VERSION 5.8 ;
BUSBITCHARS "[]" ;
DIVIDERCHAR "/" ;

UNITS
  DATABASE MICRONS 1000 ;
END UNITS
MANUFACTURINGGRID 0.001 ;

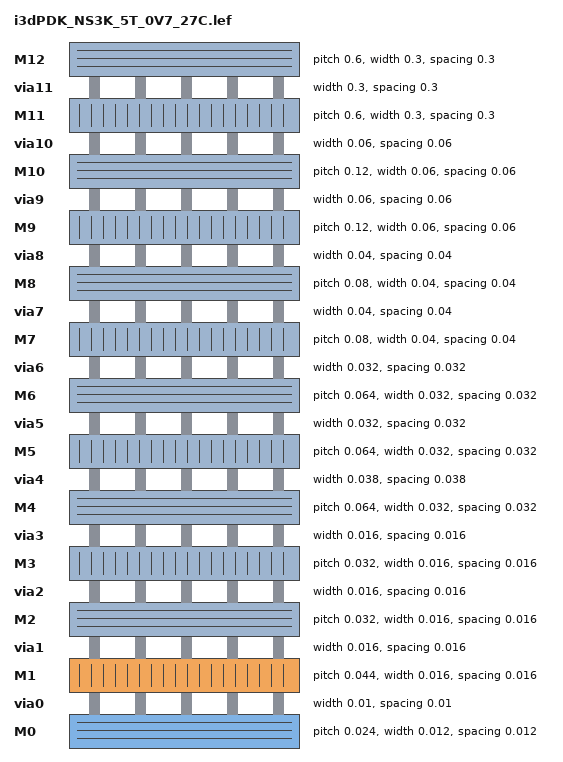
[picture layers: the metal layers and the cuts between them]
LAYER M0
  TYPE ROUTING ;
  DIRECTION HORIZONTAL ;
  PITCH 0.024 0.024 ;
  WIDTH 0.012 ;
  OFFSET 0.012 0.012 ;
  AREA 0.000144 ;
  SPACING 0.012 ;
  MAXWIDTH 5 ;
  RESISTANCE RPERSQ 2.53 ;
END M0

LAYER via0
  TYPE CUT ;
  SPACING 0.01 ;
  WIDTH 0.01 ;
  RESISTANCE 19.304 ;
END via0

LAYER M1
  TYPE ROUTING ;
  DIRECTION VERTICAL ;
  PITCH 0.044 0.044 ;
  WIDTH 0.016 ;
  OFFSET 0.016 0.016 ;
  AREA 0.000256 ;
  SPACING 0.016 ;
  MAXWIDTH 5 ;
  RESISTANCE RPERSQ 1.41 ;
END M1

LAYER via1
  TYPE CUT ;
  SPACING 0.016 ;
  WIDTH 0.016 ;
  RESISTANCE 8.56 ;
END via1

LAYER M2
  TYPE ROUTING ;
  DIRECTION HORIZONTAL ;
  PITCH 0.032 0.032 ;
  WIDTH 0.016 ;
  OFFSET 0.016 0.016 ;
  AREA 0.000256 ;
  SPACING 0.016 ;
  MAXWIDTH 5 ;
  RESISTANCE RPERSQ 1.41 ;
END M2

LAYER via2
  TYPE CUT ;
  SPACING 0.016 ;
  WIDTH 0.016 ;
  RESISTANCE 8.56 ;
END via2

LAYER M3
  TYPE ROUTING ;
  DIRECTION VERTICAL ;
  PITCH 0.032 0.032 ;
  WIDTH 0.016 ;
  OFFSET 0.016 0.016 ;
  AREA 0.000256 ;
  SPACING 0.016 ;
  MAXWIDTH 5 ;
  RESISTANCE RPERSQ 1.41 ;
END M3

LAYER via3
  TYPE CUT ;
  SPACING 0.016 ;
  WIDTH 0.016 ;
  RESISTANCE 8.56 ;
END via3

LAYER M4
  TYPE ROUTING ;
  DIRECTION HORIZONTAL ;
  PITCH 0.064 0.064 ;
  WIDTH 0.032 ;
  OFFSET 0.032 0.032 ;
  AREA 0.001024 ;
  SPACING 0.032 ;
  MAXWIDTH 5 ;
  RESISTANCE RPERSQ 0.52 ;
END M4

LAYER via4
  TYPE CUT ;
  SPACING 0.038 ;
  WIDTH 0.038 ;
  RESISTANCE 2.82 ;
END via4

LAYER M5
  TYPE ROUTING ;
  DIRECTION VERTICAL ;
  PITCH 0.064 0.064 ;
  WIDTH 0.032 ;
  OFFSET 0.032 0.032 ;
  AREA 0.001024 ;
  SPACING 0.032 ;
  MAXWIDTH 5 ;
  RESISTANCE RPERSQ 0.52 ;
END M5

LAYER via5
  TYPE CUT ;
  SPACING 0.032 ;
  WIDTH 0.032 ;
  RESISTANCE 2.82 ;
END via5

LAYER M6
  TYPE ROUTING ;
  DIRECTION HORIZONTAL ;
  PITCH 0.064 0.064 ;
  WIDTH 0.032 ;
  OFFSET 0.032 0.032 ;
  AREA 0.001024 ;
  SPACING 0.032 ;
  MAXWIDTH 5 ;
  RESISTANCE RPERSQ 0.52 ;
END M6

LAYER via6
  TYPE CUT ;
  SPACING 0.032 ;
  WIDTH 0.032 ;
  RESISTANCE 2.82 ;
END via6

LAYER M7
  TYPE ROUTING ;
  DIRECTION VERTICAL ;
  PITCH 0.08 0.08 ;
  WIDTH 0.04 ;
  OFFSET 0.04 0.04 ;
  AREA 0.0016 ;
  SPACING 0.04 ;
  MAXWIDTH 5 ;
  RESISTANCE RPERSQ 0.386 ;
END M7

LAYER via7
  TYPE CUT ;
  SPACING 0.04 ;
  WIDTH 0.04 ;
  RESISTANCE 2.02 ;
END via7

LAYER M8
  TYPE ROUTING ;
  DIRECTION HORIZONTAL ;
  PITCH 0.08 0.08 ;
  WIDTH 0.04 ;
  OFFSET 0.04 0.04 ;
  AREA 0.0016 ;
  SPACING 0.04 ;
  MAXWIDTH 5 ;
  RESISTANCE RPERSQ 0.386 ;
END M8

LAYER via8
  TYPE CUT ;
  SPACING 0.04 ;
  WIDTH 0.04 ;
  RESISTANCE 2.02 ;
END via8

LAYER M9
  TYPE ROUTING ;
  DIRECTION VERTICAL ;
  PITCH 0.12 0.12 ;
  WIDTH 0.06 ;
  OFFSEt 0.06 0.06 ;
  AREA 0.0036 ;
  SPACING 0.06 ;
  MAXWIDTH 5 ;
  RESISTANCE RPERSQ 0.23 ;
END M9

LAYER via9
  TYPE CUT ;
  SPACING 0.06 ;
  WIDTH 0.06 ;
  RESISTANCE 1.136 ;
END via9

LAYER M10
  TYPE ROUTING ;
  DIRECTION HORIZONTAL ;
  PITCH 0.12 0.12 ;
  WIDTH 0.06 ;
  OFFSET 0.06 0.06 ;
  AREA 0.0036 ;
  SPACING 0.06 ;
  MAXWIDTH 5 ;
  RESISTANCE RPERSQ 0.23 ;
END M10

LAYER via10
  TYPE CUT ;
  SPACING 0.06 ;
  WIDTH 0.06 ;
  RESISTANCE 1.136 ;
END via10

LAYER M11
  TYPE ROUTING ;
  DIRECTION VERTICAL ;
  PITCH 0.6 0.6 ;
  WIDTH 0.3 ;
  OFFSET 0.3 0.3 ;
  AREA 0.09 ;
  SPACING 0.3 ;
  MAXWIDTH 5 ;
  RESISTANCE RPERSQ 0.037 ;
END M11

LAYER via11
  TYPE CUT ;
  SPACING 0.3 ;
  WIDTH 0.3 ;
  RESISTANCE 0.158 ;
END via11

LAYER M12
  TYPE ROUTING ;
  DIRECTION HORIZONTAL ;
  PITCH 0.6 0.6 ;
  WIDTH 0.3 ;
  OFFSET 0.3 0.3 ;
  AREA 0.09 ;
  SPACING 0.3 ;
  MAXWIDTH 5 ;
  RESISTANCE RPERSQ 0.037 ;
END M12

SITE i3d_nsfet3nm
  SYMMETRY y ;
  CLASS core ;
  SIZE 0.044 BY 0.12 ;
END i3d_nsfet3nm


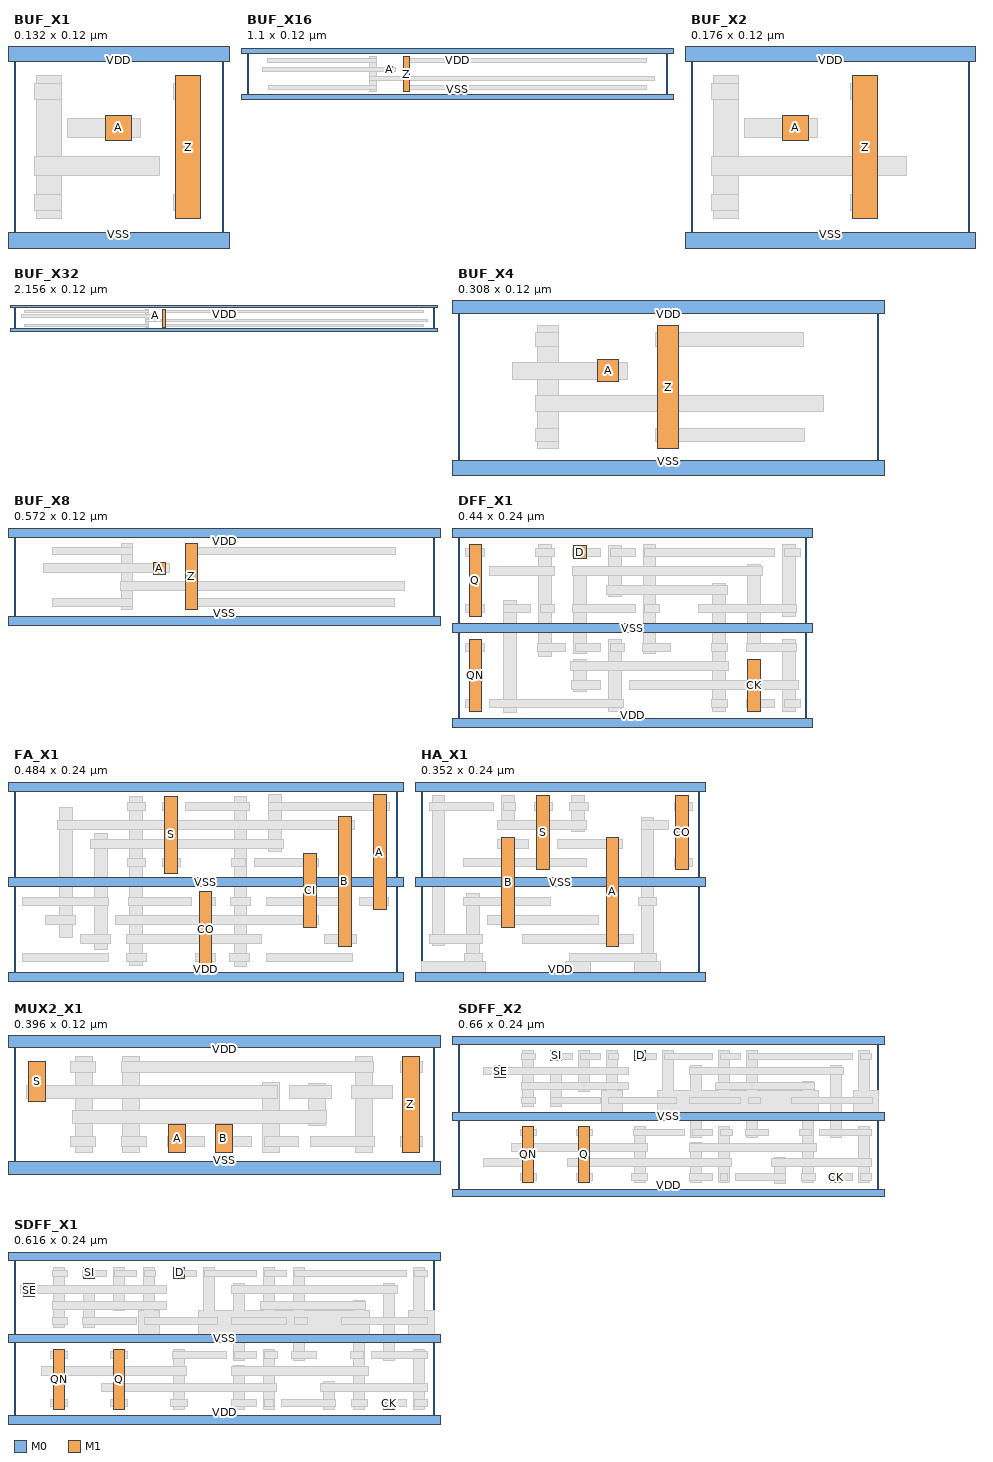
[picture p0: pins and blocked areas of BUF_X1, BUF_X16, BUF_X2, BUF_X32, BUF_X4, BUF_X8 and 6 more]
MACRO BUF_X1
  CLASS CORE ;
  ORIGIN 0 0 ;
  FOREIGN BUF_X1 0 0 ;
  SYMMETRY X Y ;
  SITE i3d_nsfet3nm ;
  SIZE 0.132 BY 0.12 ;
  PIN VDD
    DIRECTION INOUT ;
    USE POWER ;
    PORT
      LAYER M0 ;
        RECT -0.016 0.114 0.148 0.126 ;
    END
  END VDD
  PIN VSS
    DIRECTION INOUT ;
    USE GROUND ;
    PORT
      LAYER M0 ;
        RECT -0.016 -0.006 0.148 0.006 ;
    END
  END VSS
  PIN A
    DIRECTION INPUT ;
    USE SIGNAL ;
    PORT
      LAYER M1 ;
        RECT 0.058 0.064 0.074 0.08 ;
    END
  END A
  PIN Z
    DIRECTION OUTPUT ;
    USE SIGNAL ;
    PORT
      LAYER M1 ;
        RECT 0.102 0.015 0.118 0.105 ;
    END
  END Z
  OBS
    LAYER M1 DESIGNRULEWIDTH 0 ;
      RECT 0.014 0.015 0.03 0.105 ;
    LAYER M0 DESIGNRULEWIDTH 0 ;
      RECT 0.101 0.02 0.118 0.03 ;
      RECT 0.013 0.02 0.03 0.03 ;
      RECT 0.013 0.042 0.092 0.054 ;
      RECT 0.034 0.066 0.08 0.078 ;
      RECT 0.101 0.09 0.118 0.1 ;
      RECT 0.013 0.09 0.03 0.1 ;
  END
END BUF_X1

MACRO BUF_X16
  CLASS CORE ;
  ORIGIN 0 0 ;
  FOREIGN BUF_X16 0 0 ;
  SYMMETRY X Y ;
  SITE i3d_nsfet3nm ;
  SIZE 1.1 BY 0.12 ;
  PIN VDD
    DIRECTION INOUT ;
    USE POWER ;
    PORT
      LAYER M0 ;
        RECT -0.016 0.114 1.116 0.126 ;
    END
  END VDD
  PIN VSS
    DIRECTION INOUT ;
    USE GROUND ;
    PORT
      LAYER M0 ;
        RECT -0.016 -0.006 1.116 0.006 ;
    END
  END VSS
  PIN A
    DIRECTION INPUT ;
    USE SIGNAL ;
    PORT
      LAYER M1 ;
        RECT 0.366 0.064 0.382 0.08 ;
    END
  END A
  PIN Z
    DIRECTION OUTPUT ;
    USE SIGNAL ;
    PORT
      LAYER M1 ;
        RECT 0.41 0.015 0.426 0.105 ;
    END
  END Z
  OBS
    LAYER M1 DESIGNRULEWIDTH 0 ;
      RECT 0.322 0.015 0.338 0.105 ;
    LAYER M0 DESIGNRULEWIDTH 0 ;
      RECT 0.409 0.02 1.046 0.03 ;
      RECT 0.056 0.02 0.338 0.03 ;
      RECT 0.321 0.042 1.066 0.054 ;
      RECT 0.04 0.066 0.388 0.078 ;
      RECT 0.409 0.09 1.047 0.1 ;
      RECT 0.053 0.09 0.338 0.1 ;
  END
END BUF_X16

MACRO BUF_X2
  CLASS CORE ;
  ORIGIN 0 0 ;
  FOREIGN BUF_X2 0 0 ;
  SYMMETRY X Y ;
  SITE i3d_nsfet3nm ;
  SIZE 0.176 BY 0.12 ;
  PIN VDD
    DIRECTION INOUT ;
    USE POWER ;
    PORT
      LAYER M0 ;
        RECT -0.016 0.114 0.192 0.126 ;
    END
  END VDD
  PIN VSS
    DIRECTION INOUT ;
    USE GROUND ;
    PORT
      LAYER M0 ;
        RECT -0.016 -0.006 0.192 0.006 ;
    END
  END VSS
  PIN A
    DIRECTION INPUT ;
    USE SIGNAL ;
    PORT
      LAYER M1 ;
        RECT 0.058 0.064 0.074 0.08 ;
    END
  END A
  PIN Z
    DIRECTION OUTPUT ;
    USE SIGNAL ;
    PORT
      LAYER M1 ;
        RECT 0.102 0.015 0.118 0.105 ;
    END
  END Z
  OBS
    LAYER M1 DESIGNRULEWIDTH 0 ;
      RECT 0.014 0.015 0.03 0.105 ;
    LAYER M0 DESIGNRULEWIDTH 0 ;
      RECT 0.101 0.02 0.118 0.03 ;
      RECT 0.013 0.02 0.03 0.03 ;
      RECT 0.013 0.042 0.136 0.054 ;
      RECT 0.034 0.066 0.08 0.078 ;
      RECT 0.101 0.09 0.118 0.1 ;
      RECT 0.013 0.09 0.03 0.1 ;
  END
END BUF_X2

MACRO BUF_X32
  CLASS CORE ;
  ORIGIN 0 0 ;
  FOREIGN BUF_X32 0 0 ;
  SYMMETRY X Y ;
  SITE i3d_nsfet3nm ;
  SIZE 2.156 BY 0.12 ;
  PIN VDD
    DIRECTION INOUT ;
    USE POWER ;
    PORT
      LAYER M0 ;
        RECT -0.016 0.114 2.172 0.126 ;
    END
  END VDD
  PIN VSS
    DIRECTION INOUT ;
    USE GROUND ;
    PORT
      LAYER M0 ;
        RECT -0.016 -0.006 2.172 0.006 ;
    END
  END VSS
  PIN Z
    DIRECTION OUTPUT ;
    USE SIGNAL ;
    PORT
      LAYER M1 ;
        RECT 0.762 0.015 0.778 0.105 ;
    END
  END Z
  PIN A
    DIRECTION INPUT ;
    USE SIGNAL ;
    PORT
      LAYER M1 ;
        RECT 0.718 0.064 0.734 0.08 ;
    END
  END A
  OBS
    LAYER M1 DESIGNRULEWIDTH 0 ;
      RECT 0.674 0.015 0.69 0.105 ;
    LAYER M0 DESIGNRULEWIDTH 0 ;
      RECT 0.761 0.02 2.104 0.03 ;
      RECT 0.055 0.02 0.69 0.03 ;
      RECT 0.673 0.042 2.123 0.054 ;
      RECT 0.039 0.066 0.74 0.078 ;
      RECT 0.761 0.09 2.101 0.1 ;
      RECT 0.053 0.09 0.69 0.1 ;
  END
END BUF_X32

MACRO BUF_X4
  CLASS CORE ;
  ORIGIN 0 0 ;
  FOREIGN BUF_X4 0 0 ;
  SYMMETRY X Y ;
  SITE i3d_nsfet3nm ;
  SIZE 0.308 BY 0.12 ;
  PIN VDD
    DIRECTION INOUT ;
    USE POWER ;
    PORT
      LAYER M0 ;
        RECT -0.016 0.114 0.324 0.126 ;
    END
  END VDD
  PIN VSS
    DIRECTION INOUT ;
    USE GROUND ;
    PORT
      LAYER M0 ;
        RECT -0.016 -0.006 0.324 0.006 ;
    END
  END VSS
  PIN A
    DIRECTION INPUT ;
    USE SIGNAL ;
    PORT
      LAYER M1 ;
        RECT 0.102 0.064 0.118 0.08 ;
    END
  END A
  PIN Z
    DIRECTION OUTPUT ;
    USE SIGNAL ;
    PORT
      LAYER M1 ;
        RECT 0.146 0.015 0.162 0.105 ;
    END
  END Z
  OBS
    LAYER M1 DESIGNRULEWIDTH 0 ;
      RECT 0.058 0.015 0.074 0.105 ;
    LAYER M0 DESIGNRULEWIDTH 0 ;
      RECT 0.145 0.02 0.254 0.03 ;
      RECT 0.057 0.02 0.074 0.03 ;
      RECT 0.057 0.042 0.268 0.054 ;
      RECT 0.04 0.066 0.124 0.078 ;
      RECT 0.145 0.09 0.253 0.1 ;
      RECT 0.057 0.09 0.074 0.1 ;
  END
END BUF_X4

MACRO BUF_X8
  CLASS CORE ;
  ORIGIN 0 0 ;
  FOREIGN BUF_X8 0 0 ;
  SYMMETRY X Y ;
  SITE i3d_nsfet3nm ;
  SIZE 0.572 BY 0.12 ;
  PIN VDD
    DIRECTION INOUT ;
    USE POWER ;
    PORT
      LAYER M0 ;
        RECT -0.016 0.114 0.588 0.126 ;
    END
  END VDD
  PIN VSS
    DIRECTION INOUT ;
    USE GROUND ;
    PORT
      LAYER M0 ;
        RECT -0.016 -0.006 0.588 0.006 ;
    END
  END VSS
  PIN A
    DIRECTION INPUT ;
    USE SIGNAL ;
    PORT
      LAYER M1 ;
        RECT 0.19 0.064 0.206 0.08 ;
    END
  END A
  PIN Z
    DIRECTION OUTPUT ;
    USE SIGNAL ;
    PORT
      LAYER M1 ;
        RECT 0.234 0.015 0.25 0.105 ;
    END
  END Z
  OBS
    LAYER M1 DESIGNRULEWIDTH 0 ;
      RECT 0.146 0.015 0.162 0.105 ;
    LAYER M0 DESIGNRULEWIDTH 0 ;
      RECT 0.233 0.02 0.518 0.03 ;
      RECT 0.052 0.02 0.162 0.03 ;
      RECT 0.145 0.042 0.532 0.054 ;
      RECT 0.04 0.066 0.212 0.078 ;
      RECT 0.233 0.09 0.519 0.1 ;
      RECT 0.052 0.09 0.162 0.1 ;
  END
END BUF_X8

MACRO DFF_X1
  CLASS CORE ;
  ORIGIN 0 0 ;
  FOREIGN DFF_X1 0 0 ;
  SYMMETRY X Y ;
  SITE i3d_nsfet3nm ;
  SIZE 0.44 BY 0.24 ;
  PIN Q
    DIRECTION OUTPUT ;
    USE SIGNAL ;
    PORT
      LAYER M1 ;
        RECT 0.014 0.135 0.03 0.225 ;
    END
  END Q
  PIN VDD
    DIRECTION INOUT ;
    USE POWER ;
    PORT
      LAYER M0 ;
        RECT -0.016 0.234 0.456 0.246 ;
        RECT -0.016 -0.006 0.456 0.006 ;
    END
  END VDD
  PIN VSS
    DIRECTION INOUT ;
    USE GROUND ;
    PORT
      LAYER M0 ;
        RECT -0.016 0.114 0.456 0.126 ;
    END
  END VSS
  PIN D
    DIRECTION INPUT ;
    USE SIGNAL ;
    PORT
      LAYER M1 ;
        RECT 0.146 0.208 0.162 0.224 ;
    END
  END D
  PIN QN
    DIRECTION OUTPUT ;
    USE SIGNAL ;
    PORT
      LAYER M1 ;
        RECT 0.014 0.015 0.03 0.105 ;
    END
  END QN
  PIN CK
    DIRECTION INPUT ;
    USE SIGNAL ;
    PORT
      LAYER M1 ;
        RECT 0.366 0.015 0.382 0.08 ;
    END
  END CK
  OBS
    LAYER M1 ;
      RECT 0.058 0.013 0.074 0.155 ;
      RECT 0.19 0.015 0.206 0.105 ;
      RECT 0.322 0.015 0.338 0.176 ;
      RECT 0.41 0.015 0.426 0.105 ;
      RECT 0.146 0.04 0.162 0.08 ;
      RECT 0.102 0.084 0.118 0.225 ;
      RECT 0.146 0.088 0.162 0.188 ;
      RECT 0.234 0.088 0.25 0.225 ;
      RECT 0.366 0.1 0.382 0.2 ;
      RECT 0.41 0.135 0.426 0.225 ;
      RECT 0.19 0.16 0.206 0.224 ;
    LAYER M0 ;
      RECT 0.01 0.02 0.028 0.03 ;
      RECT 0.04 0.02 0.209 0.03 ;
      RECT 0.32 0.02 0.34 0.03 ;
      RECT 0.365 0.02 0.4 0.03 ;
      RECT 0.412 0.02 0.432 0.03 ;
      RECT 0.143 0.042 0.18 0.054 ;
      RECT 0.216 0.042 0.43 0.054 ;
      RECT 0.142 0.066 0.342 0.078 ;
      RECT 0.01 0.09 0.034 0.1 ;
      RECT 0.1 0.09 0.136 0.1 ;
      RECT 0.148 0.09 0.18 0.1 ;
      RECT 0.192 0.09 0.21 0.1 ;
      RECT 0.233 0.09 0.268 0.1 ;
      RECT 0.32 0.09 0.34 0.1 ;
      RECT 0.364 0.09 0.428 0.1 ;
      RECT 0.01 0.14 0.034 0.15 ;
      RECT 0.057 0.14 0.092 0.15 ;
      RECT 0.104 0.14 0.122 0.15 ;
      RECT 0.144 0.14 0.224 0.15 ;
      RECT 0.236 0.14 0.255 0.15 ;
      RECT 0.304 0.14 0.428 0.15 ;
      RECT 0.187 0.162 0.34 0.174 ;
      RECT 0.04 0.186 0.122 0.198 ;
      RECT 0.145 0.186 0.384 0.198 ;
      RECT 0.01 0.21 0.034 0.22 ;
      RECT 0.098 0.21 0.122 0.22 ;
      RECT 0.144 0.21 0.18 0.22 ;
      RECT 0.192 0.21 0.224 0.22 ;
      RECT 0.236 0.21 0.4 0.22 ;
      RECT 0.412 0.21 0.432 0.22 ;
  END
END DFF_X1


MACRO FA_X1
  CLASS CORE ;
  ORIGIN 0 0 ;
  FOREIGN FA 0 0 ;
  SYMMETRY X Y ;
  SITE i3d_nsfet3nm ;
  SIZE 0.484 BY 0.24 ;
  PIN VDD
    DIRECTION INOUT ;
    USE POWER ;
    PORT
      LAYER M0 ;
        RECT -0.016 -0.006 0.5 0.006 ;
        RECT -0.016 0.234 0.5 0.246 ;
    END
  END VDD
  PIN VSS
    DIRECTION INOUT ;
    USE GROUND ;
    PORT
      LAYER M0 ;
        RECT -0.016 0.114 0.5 0.126 ;
    END
  END VSS
  PIN CO
    DIRECTION OUTPUT ;
    USE SIGNAL ;
    PORT
      LAYER M1 ;
        RECT 0.234 0.013 0.25 0.108 ;
    END
  END CO
  PIN CI
    DIRECTION INPUT ;
    USE SIGNAL ;
    PORT
      LAYER M1 ;
        RECT 0.366 0.063 0.382 0.156 ;
    END
  END CI
  PIN A
    DIRECTION INPUT ;
    USE SIGNAL ;
    PORT
      LAYER M1 ;
        RECT 0.454 0.085 0.47 0.23 ;
    END
  END A
  PIN B
    DIRECTION INPUT ;
    USE SIGNAL ;
    PORT
      LAYER M1 ;
        RECT 0.41 0.039 0.426 0.203 ;
    END
  END B
  PIN S
    DIRECTION OUTPUT ;
    USE SIGNAL ;
    PORT
      LAYER M1 ;
        RECT 0.19 0.131 0.206 0.228 ;
    END
  END S
  OBS
    LAYER M1 DESIGNRULEWIDTH 0 ;
      RECT 0.278 0.013 0.294 0.228 ;
      RECT 0.146 0.014 0.162 0.228 ;
      RECT 0.102 0.035 0.118 0.181 ;
      RECT 0.058 0.05 0.074 0.214 ;
      RECT 0.322 0.159 0.338 0.23 ;
    LAYER M0 DESIGNRULEWIDTH 0 ;
      RECT 0.319 0.02 0.427 0.03 ;
      RECT 0.272 0.02 0.297 0.03 ;
      RECT 0.229 0.02 0.254 0.03 ;
      RECT 0.142 0.02 0.167 0.03 ;
      RECT 0.011 0.02 0.119 0.03 ;
      RECT 0.392 0.042 0.432 0.054 ;
      RECT 0.142 0.042 0.312 0.054 ;
      RECT 0.084 0.042 0.122 0.054 ;
      RECT 0.128 0.066 0.384 0.078 ;
      RECT 0.04 0.066 0.078 0.078 ;
      RECT 0.436 0.09 0.473 0.1 ;
      RECT 0.319 0.09 0.424 0.1 ;
      RECT 0.274 0.09 0.299 0.1 ;
      RECT 0.236 0.09 0.254 0.1 ;
      RECT 0.144 0.09 0.224 0.1 ;
      RECT 0.011 0.09 0.119 0.1 ;
      RECT 0.304 0.14 0.384 0.15 ;
      RECT 0.275 0.14 0.292 0.15 ;
      RECT 0.187 0.14 0.21 0.15 ;
      RECT 0.143 0.14 0.166 0.15 ;
      RECT 0.097 0.162 0.34 0.174 ;
      RECT 0.055 0.186 0.43 0.198 ;
      RECT 0.321 0.21 0.474 0.22 ;
      RECT 0.216 0.21 0.298 0.22 ;
      RECT 0.187 0.21 0.204 0.22 ;
      RECT 0.143 0.21 0.166 0.22 ;
  END
END FA_X1

MACRO HA_X1
  CLASS CORE ;
  ORIGIN 0 0 ;
  FOREIGN HA 0 0 ;
  SYMMETRY X Y ;
  SITE i3d_nsfet3nm ;
  SIZE 0.352 BY 0.24 ;
  PIN VDD
    DIRECTION INOUT ;
    USE POWER ;
    PORT
      LAYER M0 ;
        RECT -0.016 -0.006 0.368 0.006 ;
        RECT -0.016 0.234 0.368 0.246 ;
    END
  END VDD
  PIN S
    DIRECTION OUTPUT ;
    USE SIGNAL ;
    PORT
      LAYER M1 ;
        RECT 0.146 0.136 0.162 0.229 ;
    END
  END S
  PIN B
    DIRECTION INPUT ;
    USE SIGNAL ;
    PORT
      LAYER M1 ;
        RECT 0.102 0.063 0.118 0.176 ;
    END
  END B
  PIN A
    DIRECTION INPUT ;
    USE SIGNAL ;
    PORT
      LAYER M1 ;
        RECT 0.234 0.039 0.25 0.176 ;
    END
  END A
  PIN VSS
    DIRECTION INOUT ;
    USE GROUND ;
    PORT
      LAYER M0 ;
        RECT -0.016 0.114 0.368 0.126 ;
    END
  END VSS
  PIN CO
    DIRECTION OUTPUT ;
    USE SIGNAL ;
    PORT
      LAYER M1 ;
        RECT 0.322 0.136 0.338 0.229 ;
    END
  END CO
  OBS
    LAYER M1 DESIGNRULEWIDTH 0 ;
      POLYGON 0.302 0 0.302 0.019 0.294 0.019 0.294 0.201 0.278 0.201 0.278 0.019 0.27 0.019 0.27 0 ;
      RECT 0.182 0 0.214 0.019 ;
      POLYGON 0.082 0 0.082 0.019 0.074 0.019 0.074 0.105 0.058 0.105 0.058 0.019 0 0.019 0 0 ;
      RECT 0.014 0.04 0.03 0.229 ;
      RECT 0.19 0.184 0.206 0.229 ;
      RECT 0.102 0.196 0.118 0.229 ;
    LAYER M0 DESIGNRULEWIDTH 0 ;
      RECT 0.187 0.02 0.298 0.03 ;
      RECT 0.055 0.02 0.078 0.03 ;
      RECT 0.128 0.042 0.268 0.054 ;
      RECT 0.011 0.042 0.078 0.054 ;
      RECT 0.084 0.066 0.224 0.078 ;
      RECT 0.275 0.09 0.298 0.1 ;
      RECT 0.054 0.09 0.164 0.1 ;
      RECT 0.32 0.14 0.343 0.15 ;
      RECT 0.054 0.14 0.209 0.15 ;
      RECT 0.172 0.162 0.254 0.174 ;
      RECT 0.097 0.162 0.136 0.174 ;
      RECT 0.278 0.186 0.312 0.198 ;
      RECT 0.097 0.186 0.209 0.198 ;
      RECT 0.32 0.21 0.343 0.22 ;
      RECT 0.188 0.21 0.211 0.22 ;
      RECT 0.143 0.21 0.166 0.22 ;
      RECT 0.104 0.21 0.119 0.22 ;
      RECT 0.011 0.21 0.092 0.22 ;
  END
END HA_X1

MACRO MUX2_X1
  CLASS CORE ;
  ORIGIN 0 0 ;
  FOREIGN MUX2_X1 0 0 ;
  SYMMETRY X Y ;
  SITE i3d_nsfet3nm ;
  SIZE 0.396 BY 0.12 ;
  PIN VDD
    DIRECTION INOUT ;
    USE POWER ;
    PORT
      LAYER M0 ;
        RECT -0.016 0.114 0.412 0.126 ;
    END
  END VDD
  PIN VSS
    DIRECTION INOUT ;
    USE GROUND ;
    PORT
      LAYER M0 ;
        RECT -0.016 -0.006 0.412 0.006 ;
    END
  END VSS
  PIN A
    DIRECTION INPUT ;
    USE SIGNAL ;
    PORT
      LAYER M1 ;
        RECT 0.146 0.015 0.162 0.041 ;
    END
  END A
  PIN B
    DIRECTION INPUT ;
    USE SIGNAL ;
    PORT
      LAYER M1 ;
        RECT 0.19 0.015 0.206 0.041 ;
    END
  END B
  PIN S
    DIRECTION INPUT ;
    USE SIGNAL ;
    PORT
      LAYER M1 ;
        RECT 0.014 0.063 0.03 0.1 ;
    END
  END S
  PIN Z
    DIRECTION OUTPUT ;
    USE SIGNAL ;
    PORT
      LAYER M1 ;
        RECT 0.366 0.015 0.382 0.105 ;
    END
  END Z
  OBS
    LAYER M1 DESIGNRULEWIDTH 0 ;
      RECT 0.322 0.015 0.338 0.105 ;
      RECT 0.234 0.015 0.25 0.081 ;
      RECT 0.102 0.015 0.118 0.105 ;
      RECT 0.058 0.015 0.074 0.105 ;
      RECT 0.278 0.04 0.294 0.08 ;
    LAYER M0 DESIGNRULEWIDTH 0 ;
      RECT 0.364 0.02 0.385 0.03 ;
      RECT 0.28 0.02 0.34 0.03 ;
      RECT 0.236 0.02 0.268 0.03 ;
      RECT 0.192 0.02 0.224 0.03 ;
      RECT 0.145 0.02 0.18 0.03 ;
      RECT 0.101 0.02 0.125 0.03 ;
      RECT 0.053 0.02 0.077 0.03 ;
      RECT 0.055 0.042 0.295 0.054 ;
      RECT 0.318 0.066 0.357 0.078 ;
      RECT 0.26 0.066 0.299 0.078 ;
      RECT 0.012 0.066 0.248 0.078 ;
      RECT 0.364 0.09 0.385 0.1 ;
      RECT 0.101 0.09 0.339 0.1 ;
      RECT 0.053 0.09 0.077 0.1 ;
  END
END MUX2_X1

MACRO SDFF_X2
  CLASS CORE ;
  ORIGIN 0 0 ;
  FOREIGN SDFF_X2 0 0 ;
  SYMMETRY X Y ;
  SITE i3d_nsfet3nm ;
  SIZE 0.66 BY 0.24 ;
  PIN VDD
    DIRECTION INOUT ;
    USE POWER ;
    PORT
      LAYER M0 ;
        RECT -0.016 -0.006 0.676 0.006 ;
        RECT -0.016 0.234 0.676 0.246 ;
    END
  END VDD
  PIN VSS
    DIRECTION INOUT ;
    USE GROUND ;
    PORT
      LAYER M0 ;
        RECT -0.016 0.114 0.676 0.126 ;
    END
  END VSS
  PIN Q
    DIRECTION OUTPUT ;
    USE SIGNAL ;
    PORT
      LAYER M1 ;
        RECT 0.19 0.016 0.206 0.104 ;
    END
  END Q
  PIN QN
    DIRECTION OUTPUT ;
    USE SIGNAL ;
    PORT
      LAYER M1 ;
        RECT 0.102 0.016 0.118 0.104 ;
    END
  END QN
  PIN SE
    DIRECTION INPUT ;
    USE SIGNAL ;
    PORT
      LAYER M1 ;
        RECT 0.058 0.181 0.074 0.2 ;
    END
  END SE
  PIN SI
    DIRECTION INPUT ;
    USE SIGNAL ;
    PORT
      LAYER M1 ;
        RECT 0.146 0.208 0.162 0.224 ;
    END
  END SI
  PIN D
    DIRECTION INPUT ;
    USE SIGNAL ;
    PORT
      LAYER M1 ;
        RECT 0.278 0.208 0.294 0.224 ;
    END
  END D
  PIN CK
    DIRECTION INPUT ;
    USE SIGNAL ;
    PORT
      LAYER M1 ;
        RECT 0.586 0.016 0.602 0.032 ;
    END
  END CK
  OBS
    LAYER M1 DESIGNRULEWIDTH 0 ;
      RECT 0.498 0.015 0.514 0.056 ;
      RECT 0.278 0.016 0.294 0.104 ;
      RECT 0.366 0.016 0.382 0.08 ;
      RECT 0.41 0.016 0.426 0.104 ;
      POLYGON 0.558 0.016 0.558 0.124 0.566 0.124 0.566 0.161 0.558 0.161 0.558 0.176 0.542 0.176 0.542 0.161 0.47 0.161 0.47 0.224 0.454 0.224 0.454 0.161 0.426 0.161 0.426 0.224 0.41 0.224 0.41 0.161 0.382 0.161 0.382 0.2 0.366 0.2 0.366 0.161 0.338 0.161 0.338 0.224 0.322 0.224 0.322 0.161 0.314 0.161 0.314 0.124 0.366 0.124 0.366 0.088 0.382 0.088 0.382 0.124 0.454 0.124 0.454 0.088 0.47 0.088 0.47 0.124 0.542 0.124 0.542 0.016 ;
      RECT 0.63 0.016 0.646 0.104 ;
      RECT 0.586 0.088 0.602 0.2 ;
      POLYGON 0.258 0.124 0.258 0.161 0.25 0.161 0.25 0.224 0.234 0.224 0.234 0.161 0.226 0.161 0.226 0.124 ;
      POLYGON 0.66 0.124 0.66 0.161 0.646 0.161 0.646 0.224 0.63 0.224 0.63 0.161 0.622 0.161 0.622 0.124 ;
      RECT 0.102 0.136 0.118 0.224 ;
      RECT 0.146 0.136 0.162 0.188 ;
      RECT 0.19 0.16 0.206 0.224 ;
    LAYER M0 DESIGNRULEWIDTH 0 ;
      RECT 0.098 0.02 0.123 0.03 ;
      RECT 0.186 0.02 0.211 0.03 ;
      RECT 0.273 0.02 0.298 0.03 ;
      RECT 0.363 0.02 0.4 0.03 ;
      RECT 0.412 0.02 0.424 0.03 ;
      RECT 0.436 0.02 0.515 0.03 ;
      RECT 0.539 0.02 0.562 0.03 ;
      RECT 0.583 0.02 0.62 0.03 ;
      RECT 0.632 0.02 0.65 0.03 ;
      RECT 0.04 0.042 0.106 0.054 ;
      RECT 0.172 0.042 0.429 0.054 ;
      RECT 0.493 0.042 0.65 0.054 ;
      RECT 0.084 0.066 0.297 0.078 ;
      RECT 0.363 0.066 0.564 0.078 ;
      RECT 0.098 0.09 0.123 0.1 ;
      RECT 0.186 0.09 0.211 0.1 ;
      RECT 0.276 0.09 0.356 0.1 ;
      RECT 0.368 0.09 0.4 0.1 ;
      RECT 0.412 0.09 0.431 0.1 ;
      RECT 0.451 0.09 0.488 0.1 ;
      RECT 0.537 0.09 0.556 0.1 ;
      RECT 0.568 0.09 0.65 0.1 ;
      RECT 0.1 0.14 0.122 0.15 ;
      RECT 0.145 0.14 0.224 0.15 ;
      RECT 0.236 0.14 0.343 0.15 ;
      RECT 0.363 0.14 0.444 0.15 ;
      RECT 0.456 0.14 0.475 0.15 ;
      RECT 0.524 0.14 0.651 0.15 ;
      RECT 0.1 0.162 0.268 0.174 ;
      RECT 0.405 0.162 0.56 0.174 ;
      RECT 0.04 0.186 0.268 0.198 ;
      RECT 0.363 0.186 0.606 0.198 ;
      RECT 0.1 0.21 0.122 0.22 ;
      RECT 0.145 0.21 0.18 0.22 ;
      RECT 0.192 0.21 0.224 0.22 ;
      RECT 0.236 0.21 0.252 0.22 ;
      RECT 0.28 0.21 0.312 0.22 ;
      RECT 0.324 0.21 0.4 0.22 ;
      RECT 0.412 0.21 0.444 0.22 ;
      RECT 0.456 0.21 0.62 0.22 ;
      RECT 0.632 0.21 0.65 0.22 ;
  END
END SDFF_X2

MACRO SDFF_X1
  CLASS CORE ;
  ORIGIN 0 0 ;
  FOREIGN SDFF_X1 0 0 ;
  SYMMETRY X Y ;
  SITE i3d_nsfet3nm ;
  SIZE 0.616 BY 0.24 ;
  PIN VDD
    DIRECTION INOUT ;
    USE POWER ;
    PORT
      LAYER M0 ;
        RECT -0.016 -0.006 0.632 0.006 ;
        RECT -0.016 0.234 0.632 0.246 ;
    END
  END VDD
  PIN VSS
    DIRECTION INOUT ;
    USE GROUND ;
    PORT
      LAYER M0 ;
        RECT -0.016 0.114 0.632 0.126 ;
    END
  END VSS
  PIN Q
    DIRECTION OUTPUT ;
    USE SIGNAL ;
    PORT
      LAYER M1 ;
        RECT 0.146 0.016 0.162 0.104 ;
    END
  END Q
  PIN QN
    DIRECTION OUTPUT ;
    USE SIGNAL ;
    PORT
      LAYER M1 ;
        RECT 0.058 0.016 0.074 0.104 ;
    END
  END QN
  PIN SE
    DIRECTION INPUT ;
    USE SIGNAL ;
    PORT
      LAYER M1 ;
        RECT 0.014 0.181 0.03 0.2 ;
    END
  END SE
  PIN SI
    DIRECTION INPUT ;
    USE SIGNAL ;
    PORT
      LAYER M1 ;
        RECT 0.102 0.208 0.118 0.224 ;
    END
  END SI
  PIN D
    DIRECTION INPUT ;
    USE SIGNAL ;
    PORT
      LAYER M1 ;
        RECT 0.234 0.208 0.25 0.224 ;
    END
  END D
  PIN CK
    DIRECTION INPUT ;
    USE SIGNAL ;
    PORT
      LAYER M1 ;
        RECT 0.542 0.016 0.558 0.032 ;
    END
  END CK
  OBS
    LAYER M1 DESIGNRULEWIDTH 0 ;
      RECT 0.454 0.015 0.47 0.056 ;
      RECT 0.586 0.016 0.602 0.104 ;
      POLYGON 0.514 0.016 0.514 0.124 0.522 0.124 0.522 0.161 0.514 0.161 0.514 0.176 0.498 0.176 0.498 0.161 0.426 0.161 0.426 0.224 0.41 0.224 0.41 0.161 0.382 0.161 0.382 0.224 0.366 0.224 0.366 0.161 0.338 0.161 0.338 0.2 0.322 0.2 0.322 0.161 0.294 0.161 0.294 0.224 0.278 0.224 0.278 0.161 0.27 0.161 0.27 0.124 0.322 0.124 0.322 0.088 0.338 0.088 0.338 0.124 0.41 0.124 0.41 0.088 0.426 0.088 0.426 0.124 0.498 0.124 0.498 0.016 ;
      RECT 0.366 0.016 0.382 0.104 ;
      RECT 0.322 0.016 0.338 0.08 ;
      RECT 0.234 0.016 0.25 0.104 ;
      RECT 0.542 0.088 0.558 0.2 ;
      POLYGON 0.616 0.124 0.616 0.161 0.602 0.161 0.602 0.224 0.586 0.224 0.586 0.161 0.578 0.161 0.578 0.124 ;
      POLYGON 0.214 0.124 0.214 0.161 0.206 0.161 0.206 0.224 0.19 0.224 0.19 0.161 0.182 0.161 0.182 0.124 ;
      RECT 0.102 0.136 0.118 0.188 ;
      RECT 0.058 0.136 0.074 0.224 ;
      RECT 0.146 0.16 0.162 0.224 ;
    LAYER M0 DESIGNRULEWIDTH 0 ;
      RECT 0.588 0.02 0.606 0.03 ;
      RECT 0.539 0.02 0.576 0.03 ;
      RECT 0.495 0.02 0.518 0.03 ;
      RECT 0.392 0.02 0.471 0.03 ;
      RECT 0.368 0.02 0.38 0.03 ;
      RECT 0.319 0.02 0.356 0.03 ;
      RECT 0.229 0.02 0.254 0.03 ;
      RECT 0.142 0.02 0.167 0.03 ;
      RECT 0.054 0.02 0.079 0.03 ;
      RECT 0.449 0.042 0.606 0.054 ;
      RECT 0.128 0.042 0.385 0.054 ;
      RECT 0.319 0.066 0.52 0.078 ;
      RECT 0.04 0.066 0.253 0.078 ;
      RECT 0.524 0.09 0.606 0.1 ;
      RECT 0.493 0.09 0.512 0.1 ;
      RECT 0.407 0.09 0.444 0.1 ;
      RECT 0.368 0.09 0.387 0.1 ;
      RECT 0.324 0.09 0.356 0.1 ;
      RECT 0.232 0.09 0.312 0.1 ;
      RECT 0.142 0.09 0.167 0.1 ;
      RECT 0.054 0.09 0.079 0.1 ;
      RECT 0.48 0.14 0.607 0.15 ;
      RECT 0.412 0.14 0.431 0.15 ;
      RECT 0.319 0.14 0.4 0.15 ;
      RECT 0.192 0.14 0.299 0.15 ;
      RECT 0.101 0.14 0.18 0.15 ;
      RECT 0.056 0.14 0.078 0.15 ;
      RECT 0.361 0.162 0.516 0.174 ;
      RECT 0.056 0.162 0.224 0.174 ;
      RECT 0.319 0.186 0.562 0.198 ;
      RECT 0.01 0.186 0.224 0.198 ;
      RECT 0.588 0.21 0.606 0.22 ;
      RECT 0.412 0.21 0.576 0.22 ;
      RECT 0.368 0.21 0.4 0.22 ;
      RECT 0.28 0.21 0.356 0.22 ;
      RECT 0.236 0.21 0.268 0.22 ;
      RECT 0.192 0.21 0.208 0.22 ;
      RECT 0.148 0.21 0.18 0.22 ;
      RECT 0.101 0.21 0.136 0.22 ;
      RECT 0.056 0.21 0.078 0.22 ;
  END
END SDFF_X1

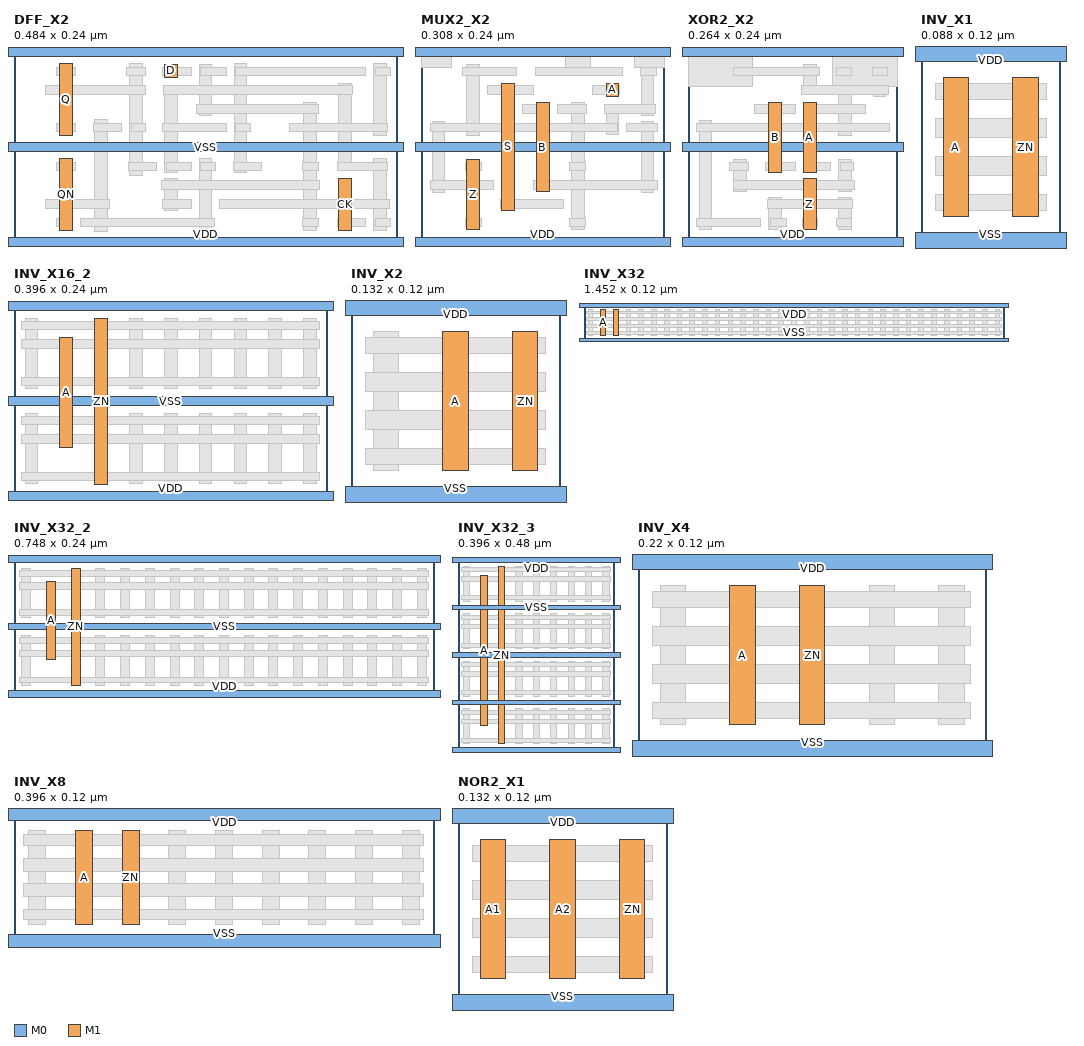
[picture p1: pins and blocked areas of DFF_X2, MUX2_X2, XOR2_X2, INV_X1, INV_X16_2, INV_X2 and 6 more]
MACRO DFF_X2
  CLASS CORE ;
  ORIGIN 0 0 ;
  FOREIGN DFF_X2 0 0 ;
  SYMMETRY X Y ;
  SITE i3d_nsfet3nm ;
  SIZE 0.484 BY 0.24 ;
  PIN VDD
    DIRECTION INOUT ;
    USE POWER ;
    PORT
      LAYER M0 ;
        RECT -0.016 -0.006 0.5 0.006 ;
        RECT -0.016 0.234 0.5 0.246 ;
    END
  END VDD
  PIN VSS
    DIRECTION INOUT ;
    USE GROUND ;
    PORT
      LAYER M0 ;
        RECT -0.016 0.114 0.5 0.126 ;
    END
  END VSS
  PIN QN
    DIRECTION OUTPUT ;
    USE SIGNAL ;
    PORT
      LAYER M1 ;
        RECT 0.058 0.015 0.074 0.105 ;
    END
  END QN
  PIN Q
    DIRECTION OUTPUT ;
    USE SIGNAL ;
    PORT
      LAYER M1 ;
        RECT 0.058 0.135 0.074 0.225 ;
    END
  END Q
  PIN CK
    DIRECTION INPUT ;
    USE SIGNAL ;
    PORT
      LAYER M1 ;
        RECT 0.41 0.015 0.426 0.08 ;
    END
  END CK
  PIN D
    DIRECTION INPUT ;
    USE SIGNAL ;
    PORT
      LAYER M1 ;
        RECT 0.19 0.208 0.206 0.224 ;
    END
  END D
  OBS
    LAYER M1 DESIGNRULEWIDTH 0 ;
      RECT 0.102 0.013 0.118 0.155 ;
      RECT 0.454 0.015 0.47 0.105 ;
      RECT 0.366 0.015 0.382 0.176 ;
      RECT 0.234 0.015 0.25 0.105 ;
      RECT 0.19 0.04 0.206 0.08 ;
      RECT 0.146 0.084 0.162 0.225 ;
      RECT 0.278 0.088 0.294 0.225 ;
      RECT 0.19 0.088 0.206 0.188 ;
      RECT 0.41 0.1 0.426 0.2 ;
      RECT 0.454 0.135 0.47 0.225 ;
      RECT 0.234 0.16 0.25 0.224 ;
    LAYER M0 DESIGNRULEWIDTH 0 ;
      RECT 0.456 0.02 0.476 0.03 ;
      RECT 0.409 0.02 0.444 0.03 ;
      RECT 0.364 0.02 0.384 0.03 ;
      RECT 0.084 0.02 0.253 0.03 ;
      RECT 0.054 0.02 0.072 0.03 ;
      RECT 0.26 0.042 0.474 0.054 ;
      RECT 0.187 0.042 0.224 0.054 ;
      RECT 0.04 0.042 0.121 0.054 ;
      RECT 0.186 0.066 0.386 0.078 ;
      RECT 0.408 0.09 0.472 0.1 ;
      RECT 0.364 0.09 0.384 0.1 ;
      RECT 0.277 0.09 0.312 0.1 ;
      RECT 0.236 0.09 0.254 0.1 ;
      RECT 0.192 0.09 0.224 0.1 ;
      RECT 0.144 0.09 0.18 0.1 ;
      RECT 0.054 0.09 0.078 0.1 ;
      RECT 0.348 0.14 0.472 0.15 ;
      RECT 0.28 0.14 0.299 0.15 ;
      RECT 0.188 0.14 0.268 0.15 ;
      RECT 0.148 0.14 0.166 0.15 ;
      RECT 0.101 0.14 0.136 0.15 ;
      RECT 0.054 0.14 0.078 0.15 ;
      RECT 0.231 0.162 0.384 0.174 ;
      RECT 0.189 0.186 0.428 0.198 ;
      RECT 0.04 0.186 0.166 0.198 ;
      RECT 0.456 0.21 0.476 0.22 ;
      RECT 0.28 0.21 0.444 0.22 ;
      RECT 0.236 0.21 0.268 0.22 ;
      RECT 0.188 0.21 0.224 0.22 ;
      RECT 0.142 0.21 0.166 0.22 ;
      RECT 0.054 0.21 0.078 0.22 ;
  END
END DFF_X2

MACRO MUX2_X2
  CLASS CORE ;
  ORIGIN 0 0 ;
  FOREIGN MUX2_X2 0 0 ;
  SYMMETRY X Y ;
  SITE i3d_nsfet3nm ;
  SIZE 0.308 BY 0.24 ;
  PIN VDD
    DIRECTION INOUT ;
    USE POWER ;
    PORT
      LAYER M0 ;
        RECT -0.016 -0.006 0.324 0.006 ;
        RECT -0.016 0.234 0.324 0.246 ;
    END
  END VDD
  PIN VSS
    DIRECTION INOUT ;
    USE GROUND ;
    PORT
      LAYER M0 ;
        RECT -0.016 0.114 0.324 0.126 ;
    END
  END VSS
  PIN Z
    DIRECTION OUTPUT ;
    USE SIGNAL ;
    PORT
      LAYER M1 ;
        RECT 0.058 0.016 0.074 0.104 ;
    END
  END Z
  PIN S
    DIRECTION INPUT ;
    USE SIGNAL ;
    PORT
      LAYER M1 ;
        RECT 0.102 0.04 0.118 0.2 ;
    END
  END S
  PIN B
    DIRECTION INPUT ;
    USE SIGNAL ;
    PORT
      LAYER M1 ;
        RECT 0.146 0.064 0.162 0.176 ;
    END
  END B
  PIN A
    DIRECTION INPUT ;
    USE SIGNAL ;
    PORT
      LAYER M1 ;
        RECT 0.234 0.184 0.25 0.2 ;
    END
  END A
  OBS
    LAYER M1 DESIGNRULEWIDTH 0 ;
      RECT 0.19 0.016 0.206 0.176 ;
      RECT 0.014 0.062 0.03 0.152 ;
      RECT 0.278 0.063 0.294 0.152 ;
      RECT 0.058 0.134 0.074 0.224 ;
      RECT 0.234 0.136 0.25 0.164 ;
      POLYGON 0.294 0.16 0.294 0.22 0.308 0.22 0.308 0.24 0.27 0.24 0.27 0.22 0.278 0.22 0.278 0.16 ;
      RECT 0.182 0.22 0.214 0.24 ;
      RECT 0 0.22 0.038 0.24 ;
    LAYER M0 DESIGNRULEWIDTH 0 ;
      RECT 0.188 0.02 0.208 0.03 ;
      RECT 0.056 0.02 0.076 0.03 ;
      RECT 0.101 0.042 0.18 0.054 ;
      RECT 0.142 0.066 0.299 0.078 ;
      RECT 0.012 0.066 0.092 0.078 ;
      RECT 0.188 0.09 0.208 0.1 ;
      RECT 0.056 0.09 0.076 0.1 ;
      RECT 0.26 0.14 0.299 0.15 ;
      RECT 0.012 0.14 0.248 0.15 ;
      RECT 0.232 0.162 0.296 0.174 ;
      RECT 0.172 0.162 0.209 0.174 ;
      RECT 0.128 0.162 0.16 0.174 ;
      RECT 0.216 0.186 0.251 0.198 ;
      RECT 0.084 0.186 0.142 0.198 ;
      RECT 0.277 0.21 0.297 0.22 ;
      RECT 0.145 0.21 0.254 0.22 ;
      RECT 0.052 0.21 0.121 0.22 ;
  END
END MUX2_X2

MACRO XOR2_X2
  CLASS CORE ;
  ORIGIN 0 0 ;
  FOREIGN XOR_X2 0 0 ;
  SYMMETRY X Y ;
  SITE i3d_nsfet3nm ;
  SIZE 0.264 BY 0.24 ;
  PIN VDD
    DIRECTION INOUT ;
    USE POWER ;
    PORT
      LAYER M0 ;
        RECT -0.016 -0.006 0.28 0.006 ;
        RECT -0.016 0.234 0.28 0.246 ;
    END
  END VDD
  PIN VSS
    DIRECTION INOUT ;
    USE GROUND ;
    PORT
      LAYER M0 ;
        RECT -0.016 0.114 0.28 0.126 ;
    END
  END VSS
  PIN Z
    DIRECTION OUTPUT ;
    USE SIGNAL ;
    PORT
      LAYER M1 ;
        RECT 0.146 0.016 0.162 0.08 ;
    END
  END Z
  PIN A
    DIRECTION INPUT ;
    USE SIGNAL ;
    PORT
      LAYER M1 ;
        RECT 0.146 0.088 0.162 0.176 ;
    END
  END A
  PIN B
    DIRECTION INPUT ;
    USE SIGNAL ;
    PORT
      LAYER M1 ;
        RECT 0.102 0.088 0.118 0.176 ;
    END
  END B
  OBS
    LAYER M1 DESIGNRULEWIDTH 0 ;
      RECT 0.19 0.016 0.206 0.056 ;
      RECT 0.102 0.016 0.118 0.056 ;
      RECT 0.014 0.016 0.03 0.154 ;
      RECT 0.19 0.064 0.206 0.104 ;
      RECT 0.058 0.064 0.074 0.104 ;
      POLYGON 0.206 0.135 0.206 0.196 0.234 0.196 0.234 0.184 0.25 0.184 0.25 0.196 0.264 0.196 0.264 0.24 0.182 0.24 0.182 0.196 0.19 0.196 0.19 0.135 ;
      RECT 0.146 0.196 0.162 0.224 ;
      RECT 0 0.196 0.082 0.24 ;
    LAYER M0 DESIGNRULEWIDTH 0 ;
      RECT 0.187 0.02 0.207 0.03 ;
      RECT 0.144 0.02 0.164 0.03 ;
      RECT 0.104 0.02 0.124 0.03 ;
      RECT 0.011 0.02 0.092 0.03 ;
      RECT 0.101 0.042 0.208 0.054 ;
      RECT 0.058 0.066 0.21 0.078 ;
      RECT 0.192 0.09 0.209 0.1 ;
      RECT 0.148 0.09 0.18 0.1 ;
      RECT 0.098 0.09 0.136 0.1 ;
      RECT 0.052 0.09 0.077 0.1 ;
      RECT 0.011 0.14 0.255 0.15 ;
      RECT 0.148 0.162 0.224 0.174 ;
      RECT 0.084 0.162 0.136 0.174 ;
      RECT 0.143 0.186 0.253 0.198 ;
      RECT 0.233 0.21 0.252 0.22 ;
      RECT 0.188 0.21 0.207 0.22 ;
      RECT 0.057 0.21 0.166 0.22 ;
  END
END XOR2_X2

MACRO INV_X1
  CLASS CORE ;
  ORIGIN 0 0 ;
  FOREIGN INV_X1 0 0 ;
  SYMMETRY X Y ;
  SITE i3d_nsfet3nm ;
  SIZE 0.088 BY 0.12 ;
  PIN VDD
    DIRECTION INOUT ;
    USE POWER ;
    PORT
      LAYER M0 ;
        RECT -0.016 0.114 0.104 0.126 ;
    END
  END VDD
  PIN VSS
    DIRECTION INOUT ;
    USE GROUND ;
    PORT
      LAYER M0 ;
        RECT -0.016 -0.006 0.104 0.006 ;
    END
  END VSS
  PIN A
    DIRECTION INPUT ;
    USE SIGNAL ;
    PORT
      LAYER M1 ;
        RECT 0.014 0.016 0.03 0.104 ;
    END
  END A
  PIN ZN
    DIRECTION OUTPUT ;
    USE SIGNAL ;
    PORT
      LAYER M1 ;
        RECT 0.058 0.016 0.074 0.104 ;
    END
  END ZN
  OBS
    LAYER M0 DESIGNRULEWIDTH 0 ;
      RECT 0.009 0.02 0.079 0.03 ;
      RECT 0.009 0.042 0.079 0.054 ;
      RECT 0.009 0.066 0.079 0.078 ;
      RECT 0.009 0.09 0.079 0.1 ;
  END
END INV_X1

MACRO INV_X16_2
  CLASS CORE ;
  ORIGIN 0 0 ;
  FOREIGN INV_X16_2 0 0 ;
  SYMMETRY X Y ;
  SITE i3d_nsfet3nm ;
  SIZE 0.396 BY 0.24 ;
  PIN VDD
    DIRECTION INOUT ;
    USE POWER ;
    PORT
      LAYER M0 ;
        RECT -0.016 -0.006 0.412 0.006 ;
        RECT -0.016 0.234 0.412 0.246 ;
    END
  END VDD
  PIN VSS
    DIRECTION INOUT ;
    USE GROUND ;
    PORT
      LAYER M0 ;
        RECT -0.016 0.114 0.412 0.126 ;
    END
  END VSS
  PIN A
    DIRECTION INPUT ;
    USE SIGNAL ;
    PORT
      LAYER M1 ;
        RECT 0.058 0.061 0.074 0.2 ;
    END
  END A
  PIN ZN
    DIRECTION OUTPUT ;
    USE SIGNAL ;
    PORT
      LAYER M1 ;
        RECT 0.102 0.015 0.118 0.224 ;
    END
  END ZN
  OBS
    LAYER M1 DESIGNRULEWIDTH 0 ;
      RECT 0.366 0.016 0.382 0.104 ;
      RECT 0.322 0.016 0.338 0.104 ;
      RECT 0.278 0.016 0.294 0.104 ;
      RECT 0.234 0.016 0.25 0.104 ;
      RECT 0.19 0.016 0.206 0.104 ;
      RECT 0.146 0.016 0.162 0.104 ;
      RECT 0.014 0.016 0.03 0.104 ;
      RECT 0.366 0.136 0.382 0.224 ;
      RECT 0.322 0.136 0.338 0.224 ;
      RECT 0.278 0.136 0.294 0.224 ;
      RECT 0.234 0.136 0.25 0.224 ;
      RECT 0.19 0.136 0.206 0.224 ;
      RECT 0.146 0.136 0.162 0.224 ;
      RECT 0.014 0.136 0.03 0.224 ;
    LAYER M0 DESIGNRULEWIDTH 0 ;
      RECT 0.009 0.02 0.386 0.03 ;
      RECT 0.009 0.066 0.386 0.078 ;
      RECT 0.009 0.09 0.386 0.1 ;
      RECT 0.009 0.14 0.386 0.15 ;
      RECT 0.009 0.186 0.386 0.198 ;
      RECT 0.009 0.21 0.386 0.22 ;
  END
END INV_X16_2

MACRO INV_X2
  CLASS CORE ;
  ORIGIN 0 0 ;
  FOREIGN INV_X2 0 0 ;
  SYMMETRY X Y ;
  SITE i3d_nsfet3nm ;
  SIZE 0.132 BY 0.12 ;
  PIN VDD
    DIRECTION INOUT ;
    USE POWER ;
    PORT
      LAYER M0 ;
        RECT -0.016 0.114 0.148 0.126 ;
    END
  END VDD
  PIN A
    DIRECTION INPUT ;
    USE SIGNAL ;
    PORT
      LAYER M1 ;
        RECT 0.058 0.016 0.074 0.104 ;
    END
  END A
  PIN ZN
    DIRECTION OUTPUT ;
    USE SIGNAL ;
    PORT
      LAYER M1 ;
        RECT 0.102 0.016 0.118 0.104 ;
    END
  END ZN
  PIN VSS
    DIRECTION INOUT ;
    USE GROUND ;
    PORT
      LAYER M0 ;
        RECT -0.016 -0.006 0.148 0.006 ;
    END
  END VSS
  OBS
    LAYER M1 DESIGNRULEWIDTH 0 ;
      RECT 0.014 0.016 0.03 0.104 ;
    LAYER M0 DESIGNRULEWIDTH 0 ;
      RECT 0.009 0.02 0.123 0.03 ;
      RECT 0.009 0.042 0.123 0.054 ;
      RECT 0.009 0.066 0.123 0.078 ;
      RECT 0.009 0.09 0.123 0.1 ;
  END
END INV_X2

MACRO INV_X32
  CLASS CORE ;
  ORIGIN 0 0 ;
  FOREIGN INV_X32 0 0 ;
  SYMMETRY X Y ;
  SITE i3d_nsfet3nm ;
  SIZE 1.452 BY 0.12 ;
  PIN VDD
    DIRECTION INOUT ;
    USE POWER ;
    PORT
      LAYER M0 ;
        RECT -0.016 0.114 1.468 0.126 ;
    END
  END VDD
  PIN VSS
    DIRECTION INOUT ;
    USE GROUND ;
    PORT
      LAYER M0 ;
        RECT -0.016 -0.006 1.468 0.006 ;
    END
  END VSS
  PIN A
    DIRECTION INPUT ;
    USE SIGNAL ;
    PORT
      LAYER M1 ;
        RECT 0.058 0.016 0.074 0.104 ;
    END
  END A
  PIN ZN
    DIRECTION OUTPUT ;
    USE SIGNAL ;
    PORT
      LAYER M1 ;
        RECT 0.102 0.016 0.118 0.104 ;
    END
  END ZN
  OBS
    LAYER M1 DESIGNRULEWIDTH 0 ;
      RECT 1.422 0.016 1.438 0.104 ;
      RECT 1.378 0.016 1.394 0.104 ;
      RECT 1.334 0.016 1.35 0.104 ;
      RECT 1.29 0.016 1.306 0.104 ;
      RECT 1.246 0.016 1.262 0.104 ;
      RECT 1.202 0.016 1.218 0.104 ;
      RECT 1.158 0.016 1.174 0.104 ;
      RECT 1.114 0.016 1.13 0.104 ;
      RECT 1.07 0.016 1.086 0.104 ;
      RECT 1.026 0.016 1.042 0.104 ;
      RECT 0.982 0.016 0.998 0.104 ;
      RECT 0.938 0.016 0.954 0.104 ;
      RECT 0.894 0.016 0.91 0.104 ;
      RECT 0.85 0.016 0.866 0.104 ;
      RECT 0.806 0.016 0.822 0.104 ;
      RECT 0.762 0.016 0.778 0.104 ;
      RECT 0.718 0.016 0.734 0.104 ;
      RECT 0.674 0.016 0.69 0.104 ;
      RECT 0.63 0.016 0.646 0.104 ;
      RECT 0.586 0.016 0.602 0.104 ;
      RECT 0.542 0.016 0.558 0.104 ;
      RECT 0.498 0.016 0.514 0.104 ;
      RECT 0.454 0.016 0.47 0.104 ;
      RECT 0.41 0.016 0.426 0.104 ;
      RECT 0.366 0.016 0.382 0.104 ;
      RECT 0.322 0.016 0.338 0.104 ;
      RECT 0.278 0.016 0.294 0.104 ;
      RECT 0.234 0.016 0.25 0.104 ;
      RECT 0.19 0.016 0.206 0.104 ;
      RECT 0.146 0.016 0.162 0.104 ;
      RECT 0.014 0.016 0.03 0.104 ;
    LAYER M0 DESIGNRULEWIDTH 0 ;
      RECT 0.009 0.02 1.442 0.03 ;
      RECT 0.009 0.042 1.442 0.054 ;
      RECT 0.009 0.066 1.442 0.078 ;
      RECT 0.009 0.09 1.442 0.1 ;
  END
END INV_X32

MACRO INV_X32_2
  CLASS CORE ;
  ORIGIN 0 0 ;
  FOREIGN INV_X32_2 0 0 ;
  SYMMETRY X Y ;
  SITE i3d_nsfet3nm ;
  SIZE 0.748 BY 0.24 ;
  PIN VDD
    DIRECTION INOUT ;
    USE POWER ;
    PORT
      LAYER M0 ;
        RECT -0.016 -0.006 0.764 0.006 ;
        RECT -0.016 0.234 0.764 0.246 ;
    END
  END VDD
  PIN VSS
    DIRECTION INOUT ;
    USE GROUND ;
    PORT
      LAYER M0 ;
        RECT -0.016 0.114 0.764 0.126 ;
    END
  END VSS
  PIN A
    DIRECTION INPUT ;
    USE SIGNAL ;
    PORT
      LAYER M1 ;
        RECT 0.058 0.061 0.074 0.2 ;
    END
  END A
  PIN ZN
    DIRECTION OUTPUT ;
    USE SIGNAL ;
    PORT
      LAYER M1 ;
        RECT 0.102 0.015 0.118 0.224 ;
    END
  END ZN
  OBS
    LAYER M1 DESIGNRULEWIDTH 0 ;
      RECT 0.718 0.016 0.734 0.104 ;
      RECT 0.674 0.016 0.69 0.104 ;
      RECT 0.63 0.016 0.646 0.104 ;
      RECT 0.586 0.016 0.602 0.104 ;
      RECT 0.542 0.016 0.558 0.104 ;
      RECT 0.498 0.016 0.514 0.104 ;
      RECT 0.454 0.016 0.47 0.104 ;
      RECT 0.41 0.016 0.426 0.104 ;
      RECT 0.366 0.016 0.382 0.104 ;
      RECT 0.322 0.016 0.338 0.104 ;
      RECT 0.278 0.016 0.294 0.104 ;
      RECT 0.234 0.016 0.25 0.104 ;
      RECT 0.19 0.016 0.206 0.104 ;
      RECT 0.146 0.016 0.162 0.104 ;
      RECT 0.014 0.016 0.03 0.104 ;
      RECT 0.718 0.136 0.734 0.224 ;
      RECT 0.674 0.136 0.69 0.224 ;
      RECT 0.63 0.136 0.646 0.224 ;
      RECT 0.586 0.136 0.602 0.224 ;
      RECT 0.542 0.136 0.558 0.224 ;
      RECT 0.498 0.136 0.514 0.224 ;
      RECT 0.454 0.136 0.47 0.224 ;
      RECT 0.41 0.136 0.426 0.224 ;
      RECT 0.366 0.136 0.382 0.224 ;
      RECT 0.322 0.136 0.338 0.224 ;
      RECT 0.278 0.136 0.294 0.224 ;
      RECT 0.234 0.136 0.25 0.224 ;
      RECT 0.19 0.136 0.206 0.224 ;
      RECT 0.146 0.136 0.162 0.224 ;
      RECT 0.014 0.136 0.03 0.224 ;
    LAYER M0 DESIGNRULEWIDTH 0 ;
      RECT 0.009 0.02 0.738 0.03 ;
      RECT 0.009 0.066 0.738 0.078 ;
      RECT 0.009 0.09 0.739 0.1 ;
      RECT 0.009 0.14 0.738 0.15 ;
      RECT 0.009 0.186 0.738 0.198 ;
      RECT 0.009 0.21 0.738 0.22 ;
  END
END INV_X32_2

MACRO INV_X32_3
  CLASS CORE ;
  ORIGIN 0 0 ;
  FOREIGN INV_X32_3 0 0 ;
  SYMMETRY X Y ;
  SITE i3d_nsfet3nm ;
  SIZE 0.396 BY 0.48 ;
  PIN VDD
    DIRECTION INOUT ;
    USE POWER ;
    PORT
      LAYER M0 ;
        RECT -0.016 -0.006 0.412 0.006 ;
        RECT -0.016 0.234 0.412 0.246 ;
        RECT -0.016 0.474 0.412 0.486 ;
    END
  END VDD
  PIN VSS
    DIRECTION INOUT ;
    USE GROUND ;
    PORT
      LAYER M0 ;
        RECT -0.016 0.114 0.412 0.126 ;
        RECT -0.016 0.354 0.412 0.366 ;
    END
  END VSS
  PIN A
    DIRECTION INPUT ;
    USE SIGNAL ;
    PORT
      LAYER M1 ;
        RECT 0.058 0.062 0.074 0.44 ;
    END
  END A
  PIN ZN
    DIRECTION OUTPUT ;
    USE SIGNAL ;
    PORT
      LAYER M1 ;
        RECT 0.102 0.016 0.118 0.464 ;
    END
  END ZN
  OBS
    LAYER M1 DESIGNRULEWIDTH 0 ;
      RECT 0.366 0.016 0.382 0.104 ;
      RECT 0.322 0.016 0.338 0.104 ;
      RECT 0.278 0.016 0.294 0.104 ;
      RECT 0.234 0.016 0.25 0.104 ;
      RECT 0.19 0.016 0.206 0.104 ;
      RECT 0.146 0.016 0.162 0.104 ;
      RECT 0.014 0.016 0.03 0.104 ;
      RECT 0.366 0.136 0.382 0.224 ;
      RECT 0.322 0.136 0.338 0.224 ;
      RECT 0.278 0.136 0.294 0.224 ;
      RECT 0.234 0.136 0.25 0.224 ;
      RECT 0.19 0.136 0.206 0.224 ;
      RECT 0.146 0.136 0.162 0.224 ;
      RECT 0.014 0.136 0.03 0.224 ;
      RECT 0.366 0.256 0.382 0.344 ;
      RECT 0.322 0.256 0.338 0.344 ;
      RECT 0.278 0.256 0.294 0.344 ;
      RECT 0.234 0.256 0.25 0.344 ;
      RECT 0.19 0.256 0.206 0.344 ;
      RECT 0.146 0.256 0.162 0.344 ;
      RECT 0.014 0.256 0.03 0.344 ;
      RECT 0.366 0.376 0.382 0.464 ;
      RECT 0.322 0.376 0.338 0.464 ;
      RECT 0.278 0.376 0.294 0.464 ;
      RECT 0.234 0.376 0.25 0.464 ;
      RECT 0.19 0.376 0.206 0.464 ;
      RECT 0.146 0.376 0.162 0.464 ;
      RECT 0.014 0.376 0.03 0.464 ;
    LAYER M0 DESIGNRULEWIDTH 0 ;
      RECT 0.009 0.02 0.386 0.03 ;
      RECT 0.009 0.066 0.386 0.078 ;
      RECT 0.009 0.09 0.386 0.1 ;
      RECT 0.009 0.14 0.386 0.15 ;
      RECT 0.009 0.186 0.386 0.198 ;
      RECT 0.009 0.21 0.386 0.22 ;
      RECT 0.009 0.26 0.386 0.27 ;
      RECT 0.009 0.306 0.386 0.318 ;
      RECT 0.009 0.33 0.386 0.34 ;
      RECT 0.009 0.38 0.386 0.39 ;
      RECT 0.009 0.426 0.386 0.438 ;
      RECT 0.009 0.45 0.386 0.46 ;
  END
END INV_X32_3

MACRO INV_X4
  CLASS CORE ;
  ORIGIN 0 0 ;
  FOREIGN INV_X4 0 0 ;
  SYMMETRY X Y ;
  SITE i3d_nsfet3nm ;
  SIZE 0.22 BY 0.12 ;
  PIN VDD
    DIRECTION INOUT ;
    USE POWER ;
    PORT
      LAYER M0 ;
        RECT -0.016 0.114 0.236 0.126 ;
    END
  END VDD
  PIN A
    DIRECTION INPUT ;
    USE SIGNAL ;
    PORT
      LAYER M1 ;
        RECT 0.058 0.016 0.074 0.104 ;
    END
  END A
  PIN ZN
    DIRECTION OUTPUT ;
    USE SIGNAL ;
    PORT
      LAYER M1 ;
        RECT 0.102 0.016 0.118 0.104 ;
    END
  END ZN
  PIN VSS
    DIRECTION INOUT ;
    USE GROUND ;
    PORT
      LAYER M0 ;
        RECT -0.016 -0.006 0.236 0.006 ;
    END
  END VSS
  OBS
    LAYER M1 DESIGNRULEWIDTH 0 ;
      RECT 0.19 0.016 0.206 0.104 ;
      RECT 0.146 0.016 0.162 0.104 ;
      RECT 0.014 0.016 0.03 0.104 ;
    LAYER M0 DESIGNRULEWIDTH 0 ;
      RECT 0.009 0.02 0.21 0.03 ;
      RECT 0.009 0.042 0.21 0.054 ;
      RECT 0.009 0.066 0.21 0.078 ;
      RECT 0.009 0.09 0.21 0.1 ;
  END
END INV_X4

MACRO INV_X8
  CLASS CORE ;
  ORIGIN 0 0 ;
  FOREIGN INV_X8 0 0 ;
  SYMMETRY X Y ;
  SITE i3d_nsfet3nm ;
  SIZE 0.396 BY 0.12 ;
  PIN VDD
    DIRECTION INOUT ;
    USE POWER ;
    PORT
      LAYER M0 ;
        RECT -0.016 0.114 0.412 0.126 ;
    END
  END VDD
  PIN A
    DIRECTION INPUT ;
    USE SIGNAL ;
    PORT
      LAYER M1 ;
        RECT 0.058 0.016 0.074 0.104 ;
    END
  END A
  PIN ZN
    DIRECTION OUTPUT ;
    USE SIGNAL ;
    PORT
      LAYER M1 ;
        RECT 0.102 0.016 0.118 0.104 ;
    END
  END ZN
  PIN VSS
    DIRECTION INOUT ;
    USE GROUND ;
    PORT
      LAYER M0 ;
        RECT -0.016 -0.006 0.412 0.006 ;
    END
  END VSS
  OBS
    LAYER M1 DESIGNRULEWIDTH 0 ;
      RECT 0.366 0.016 0.382 0.104 ;
      RECT 0.322 0.016 0.338 0.104 ;
      RECT 0.278 0.016 0.294 0.104 ;
      RECT 0.234 0.016 0.25 0.104 ;
      RECT 0.19 0.016 0.206 0.104 ;
      RECT 0.146 0.016 0.162 0.104 ;
      RECT 0.014 0.016 0.03 0.104 ;
    LAYER M0 DESIGNRULEWIDTH 0 ;
      RECT 0.009 0.02 0.386 0.03 ;
      RECT 0.009 0.042 0.386 0.054 ;
      RECT 0.009 0.066 0.386 0.078 ;
      RECT 0.009 0.09 0.386 0.1 ;
  END
END INV_X8

MACRO NOR2_X1
  CLASS CORE ;
  ORIGIN 0 0 ;
  FOREIGN NOR2_X1 0 0 ;
  SYMMETRY X Y ;
  SITE i3d_nsfet3nm ;
  SIZE 0.132 BY 0.12 ;
  PIN VDD
    DIRECTION INOUT ;
    USE POWER ;
    PORT
      LAYER M0 ;
        RECT -0.016 0.114 0.148 0.126 ;
    END
  END VDD
  PIN VSS
    DIRECTION INOUT ;
    USE GROUND ;
    PORT
      LAYER M0 ;
        RECT -0.016 -0.006 0.148 0.006 ;
    END
  END VSS
  PIN A1
    DIRECTION INPUT ;
    USE SIGNAL ;
    PORT
      LAYER M1 ;
        RECT 0.014 0.016 0.03 0.104 ;
    END
  END A1
  PIN A2
    DIRECTION INPUT ;
    USE SIGNAL ;
    PORT
      LAYER M1 ;
        RECT 0.058 0.016 0.074 0.104 ;
    END
  END A2
  PIN ZN
    DIRECTION OUTPUT ;
    USE SIGNAL ;
    PORT
      LAYER M1 ;
        RECT 0.102 0.016 0.118 0.104 ;
    END
  END ZN
  OBS
    LAYER M0 DESIGNRULEWIDTH 0 ;
      RECT 0.009 0.02 0.123 0.03 ;
      RECT 0.009 0.042 0.123 0.054 ;
      RECT 0.009 0.066 0.123 0.078 ;
      RECT 0.009 0.09 0.123 0.1 ;
  END
END NOR2_X1

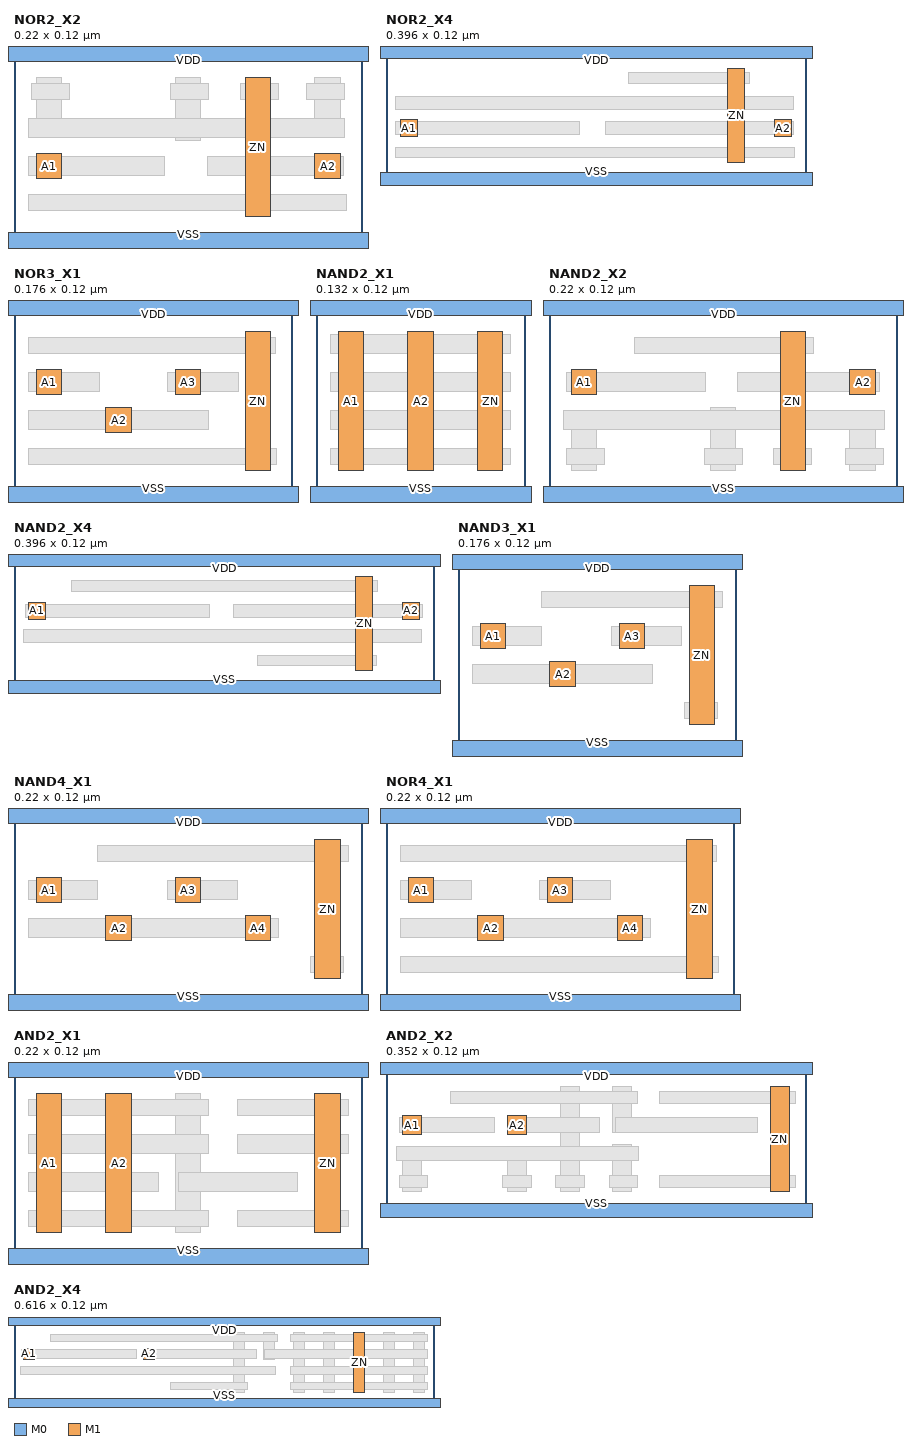
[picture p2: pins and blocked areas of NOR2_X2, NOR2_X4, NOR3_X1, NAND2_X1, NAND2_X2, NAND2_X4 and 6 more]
MACRO NOR2_X2
  CLASS CORE ;
  ORIGIN 0 0 ;
  FOREIGN NOR2_X2 0 0 ;
  SYMMETRY X Y ;
  SITE i3d_nsfet3nm ;
  SIZE 0.22 BY 0.12 ;
  PIN VDD
    DIRECTION INOUT ;
    USE POWER ;
    PORT
      LAYER M0 ;
        RECT -0.016 0.114 0.236 0.126 ;
    END
  END VDD
  PIN VSS
    DIRECTION INOUT ;
    USE GROUND ;
    PORT
      LAYER M0 ;
        RECT -0.016 -0.006 0.236 0.006 ;
    END
  END VSS
  PIN ZN
    DIRECTION OUTPUT ;
    USE SIGNAL ;
    PORT
      LAYER M1 ;
        RECT 0.146 0.016 0.162 0.104 ;
    END
  END ZN
  PIN A2
    DIRECTION INPUT ;
    USE SIGNAL ;
    PORT
      LAYER M1 ;
        RECT 0.19 0.04 0.206 0.056 ;
    END
  END A2
  PIN A1
    DIRECTION INPUT ;
    USE SIGNAL ;
    PORT
      LAYER M1 ;
        RECT 0.014 0.04 0.03 0.056 ;
    END
  END A1
  OBS
    LAYER M1 DESIGNRULEWIDTH 0 ;
      RECT 0.102 0.064 0.118 0.104 ;
      RECT 0.19 0.076 0.206 0.104 ;
      RECT 0.014 0.076 0.03 0.104 ;
    LAYER M0 DESIGNRULEWIDTH 0 ;
      RECT 0.009 0.02 0.21 0.03 ;
      RECT 0.122 0.042 0.208 0.054 ;
      RECT 0.009 0.042 0.095 0.054 ;
      RECT 0.009 0.066 0.209 0.078 ;
      RECT 0.185 0.09 0.209 0.1 ;
      RECT 0.143 0.09 0.167 0.1 ;
      RECT 0.099 0.09 0.123 0.1 ;
      RECT 0.011 0.09 0.035 0.1 ;
  END
END NOR2_X2

MACRO NOR2_X4
  CLASS CORE ;
  ORIGIN 0 0 ;
  FOREIGN NOR2_X4 0 0 ;
  SYMMETRY X Y ;
  SITE i3d_nsfet3nm ;
  SIZE 0.396 BY 0.12 ;
  PIN VDD
    DIRECTION INOUT ;
    USE POWER ;
    PORT
      LAYER M0 ;
        RECT -0.016 0.114 0.412 0.126 ;
    END
  END VDD
  PIN VSS
    DIRECTION INOUT ;
    USE GROUND ;
    PORT
      LAYER M0 ;
        RECT -0.016 -0.006 0.412 0.006 ;
    END
  END VSS
  PIN A2
    DIRECTION INPUT ;
    USE SIGNAL ;
    PORT
      LAYER M1 ;
        RECT 0.366 0.04 0.382 0.056 ;
    END
  END A2
  PIN ZN
    DIRECTION OUTPUT ;
    USE SIGNAL ;
    PORT
      LAYER M1 ;
        RECT 0.322 0.016 0.338 0.104 ;
    END
  END ZN
  PIN A1
    DIRECTION INPUT ;
    USE SIGNAL ;
    PORT
      LAYER M1 ;
        RECT 0.014 0.04 0.03 0.056 ;
    END
  END A1
  OBS
    LAYER M0 DESIGNRULEWIDTH 0 ;
      RECT 0.009 0.02 0.385 0.03 ;
      RECT 0.207 0.042 0.384 0.054 ;
      RECT 0.009 0.042 0.182 0.054 ;
      RECT 0.009 0.066 0.384 0.078 ;
      RECT 0.229 0.09 0.343 0.1 ;
  END
END NOR2_X4

MACRO NOR3_X1
  CLASS CORE ;
  ORIGIN 0 0 ;
  FOREIGN NOR3_X1 0 0 ;
  SYMMETRY X Y ;
  SITE i3d_nsfet3nm ;
  SIZE 0.176 BY 0.12 ;
  PIN VDD
    DIRECTION INOUT ;
    USE POWER ;
    PORT
      LAYER M0 ;
        RECT -0.016 0.114 0.192 0.126 ;
    END
  END VDD
  PIN VSS
    DIRECTION INOUT ;
    USE GROUND ;
    PORT
      LAYER M0 ;
        RECT -0.016 -0.006 0.192 0.006 ;
    END
  END VSS
  PIN ZN
    DIRECTION OUTPUT ;
    USE SIGNAL ;
    PORT
      LAYER M1 ;
        RECT 0.146 0.016 0.162 0.104 ;
    END
  END ZN
  PIN A1
    DIRECTION INPUT ;
    USE SIGNAL ;
    PORT
      LAYER M1 ;
        RECT 0.014 0.064 0.03 0.08 ;
    END
  END A1
  PIN A2
    DIRECTION INPUT ;
    USE SIGNAL ;
    PORT
      LAYER M1 ;
        RECT 0.058 0.04 0.074 0.056 ;
    END
  END A2
  PIN A3
    DIRECTION INPUT ;
    USE SIGNAL ;
    PORT
      LAYER M1 ;
        RECT 0.102 0.064 0.118 0.08 ;
    END
  END A3
  OBS
    LAYER M0 DESIGNRULEWIDTH 0 ;
      RECT 0.009 0.02 0.166 0.03 ;
      RECT 0.009 0.042 0.123 0.054 ;
      RECT 0.097 0.066 0.142 0.078 ;
      RECT 0.009 0.066 0.054 0.078 ;
      RECT 0.009 0.09 0.165 0.1 ;
  END
END NOR3_X1

MACRO NAND2_X1
  CLASS CORE ;
  ORIGIN 0 0 ;
  FOREIGN NAND2_X1 0 0 ;
  SYMMETRY X Y ;
  SITE i3d_nsfet3nm ;
  SIZE 0.132 BY 0.12 ;
  PIN VDD
    DIRECTION INOUT ;
    USE POWER ;
    PORT
      LAYER M0 ;
        RECT -0.016 0.114 0.148 0.126 ;
    END
  END VDD
  PIN A2
    DIRECTION INPUT ;
    USE SIGNAL ;
    PORT
      LAYER M1 ;
        RECT 0.058 0.016 0.074 0.104 ;
    END
  END A2
  PIN A1
    DIRECTION INPUT ;
    USE SIGNAL ;
    PORT
      LAYER M1 ;
        RECT 0.014 0.016 0.03 0.104 ;
    END
  END A1
  PIN ZN
    DIRECTION OUTPUT ;
    USE SIGNAL ;
    PORT
      LAYER M1 ;
        RECT 0.102 0.016 0.118 0.104 ;
    END
  END ZN
  PIN VSS
    DIRECTION INOUT ;
    USE GROUND ;
    PORT
      LAYER M0 ;
        RECT -0.016 -0.006 0.148 0.006 ;
    END
  END VSS
  OBS
    LAYER M0 DESIGNRULEWIDTH 0 ;
      RECT 0.009 0.02 0.123 0.03 ;
      RECT 0.009 0.042 0.123 0.054 ;
      RECT 0.009 0.066 0.123 0.078 ;
      RECT 0.009 0.09 0.123 0.102 ;
      RECT -0.016 0.114 0.148 0.126 ;
  END
END NAND2_X1

MACRO NAND2_X2
  CLASS CORE ;
  ORIGIN 0 0 ;
  FOREIGN NAND2_X2 0 0 ;
  SYMMETRY X Y ;
  SITE i3d_nsfet3nm ;
  SIZE 0.22 BY 0.12 ;
  PIN VDD
    DIRECTION INOUT ;
    USE POWER ;
    PORT
      LAYER M0 ;
        RECT -0.016 0.114 0.236 0.126 ;
    END
  END VDD
  PIN VSS
    DIRECTION INOUT ;
    USE GROUND ;
    PORT
      LAYER M0 ;
        RECT -0.016 -0.006 0.236 0.006 ;
    END
  END VSS
  PIN A1
    DIRECTION INPUT ;
    USE SIGNAL ;
    PORT
      LAYER M1 ;
        RECT 0.014 0.064 0.03 0.08 ;
    END
  END A1
  PIN A2
    DIRECTION INPUT ;
    USE SIGNAL ;
    PORT
      LAYER M1 ;
        RECT 0.19 0.064 0.206 0.08 ;
    END
  END A2
  PIN ZN
    DIRECTION OUTPUT ;
    USE SIGNAL ;
    PORT
      LAYER M1 ;
        RECT 0.146 0.016 0.162 0.104 ;
    END
  END ZN
  OBS
    LAYER M1 DESIGNRULEWIDTH 0 ;
      RECT 0.19 0.016 0.206 0.044 ;
      RECT 0.102 0.016 0.118 0.056 ;
      RECT 0.014 0.016 0.03 0.044 ;
    LAYER M0 DESIGNRULEWIDTH 0 ;
      RECT 0.187 0.02 0.211 0.03 ;
      RECT 0.142 0.02 0.166 0.03 ;
      RECT 0.098 0.02 0.122 0.03 ;
      RECT 0.011 0.02 0.035 0.03 ;
      RECT 0.009 0.042 0.212 0.054 ;
      RECT 0.119 0.066 0.209 0.078 ;
      RECT 0.011 0.066 0.099 0.078 ;
      RECT 0.054 0.09 0.167 0.1 ;
  END
END NAND2_X2

MACRO NAND2_X4
  CLASS CORE ;
  ORIGIN 0 0 ;
  FOREIGN NAND2_X4 0 0 ;
  SYMMETRY X Y ;
  SITE i3d_nsfet3nm ;
  SIZE 0.396 BY 0.12 ;
  PIN VDD
    DIRECTION INOUT ;
    USE POWER ;
    PORT
      LAYER M0 ;
        RECT -0.016 0.114 0.412 0.126 ;
    END
  END VDD
  PIN VSS
    DIRECTION INOUT ;
    USE GROUND ;
    PORT
      LAYER M0 ;
        RECT -0.016 -0.006 0.412 0.006 ;
    END
  END VSS
  PIN A1
    DIRECTION INPUT ;
    USE SIGNAL ;
    PORT
      LAYER M1 ;
        RECT 0.014 0.064 0.03 0.08 ;
    END
  END A1
  PIN A2
    DIRECTION INPUT ;
    USE SIGNAL ;
    PORT
      LAYER M1 ;
        RECT 0.366 0.064 0.382 0.08 ;
    END
  END A2
  PIN ZN
    DIRECTION OUTPUT ;
    USE SIGNAL ;
    PORT
      LAYER M1 ;
        RECT 0.322 0.016 0.338 0.104 ;
    END
  END ZN
  OBS
    LAYER M0 DESIGNRULEWIDTH 0 ;
      RECT 0.23 0.02 0.342 0.03 ;
      RECT 0.009 0.042 0.384 0.054 ;
      RECT 0.207 0.066 0.385 0.078 ;
      RECT 0.011 0.066 0.184 0.078 ;
      RECT 0.054 0.09 0.343 0.1 ;
  END
END NAND2_X4

MACRO NAND3_X1
  CLASS CORE ;
  ORIGIN 0 0 ;
  FOREIGN NAND3_X1 0 0 ;
  SYMMETRY X Y ;
  SITE i3d_nsfet3nm ;
  SIZE 0.176 BY 0.12 ;
  PIN VDD
    DIRECTION INOUT ;
    USE POWER ;
    PORT
      LAYER M0 ;
        RECT -0.016 0.114 0.192 0.126 ;
    END
  END VDD
  PIN VSS
    DIRECTION INOUT ;
    USE GROUND ;
    PORT
      LAYER M0 ;
        RECT -0.016 -0.006 0.192 0.006 ;
    END
  END VSS
  PIN A1
    DIRECTION INPUT ;
    USE SIGNAL ;
    PORT
      LAYER M1 ;
        RECT 0.014 0.064 0.03 0.08 ;
    END
  END A1
  PIN A3
    DIRECTION INPUT ;
    USE SIGNAL ;
    PORT
      LAYER M1 ;
        RECT 0.102 0.064 0.118 0.08 ;
    END
  END A3
  PIN A2
    DIRECTION INPUT ;
    USE SIGNAL ;
    PORT
      LAYER M1 ;
        RECT 0.058 0.04 0.074 0.056 ;
    END
  END A2
  PIN ZN
    DIRECTION OUTPUT ;
    USE SIGNAL ;
    PORT
      LAYER M1 ;
        RECT 0.146 0.016 0.162 0.104 ;
    END
  END ZN
  OBS
    LAYER M0 DESIGNRULEWIDTH 0 ;
      RECT 0.143 0.02 0.164 0.03 ;
      RECT 0.009 0.042 0.123 0.054 ;
      RECT 0.097 0.066 0.141 0.078 ;
      RECT 0.009 0.066 0.053 0.078 ;
      RECT 0.053 0.09 0.167 0.1 ;
  END
END NAND3_X1

MACRO NAND4_X1
  CLASS CORE ;
  ORIGIN 0 0 ;
  FOREIGN NAND4_X1 0 0 ;
  SYMMETRY X Y ;
  SITE i3d_nsfet3nm ;
  SIZE 0.22 BY 0.12 ;
  PIN VSS
    DIRECTION INOUT ;
    USE GROUND ;
    PORT
      LAYER M0 ;
        RECT -0.016 -0.006 0.236 0.006 ;
    END
  END VSS
  PIN VDD
    DIRECTION INOUT ;
    USE POWER ;
    PORT
      LAYER M0 ;
        RECT -0.016 0.114 0.236 0.126 ;
    END
  END VDD
  PIN A1
    DIRECTION INPUT ;
    USE SIGNAL ;
    PORT
      LAYER M1 ;
        RECT 0.014 0.064 0.03 0.08 ;
    END
  END A1
  PIN A2
    DIRECTION INPUT ;
    USE SIGNAL ;
    PORT
      LAYER M1 ;
        RECT 0.058 0.04 0.074 0.056 ;
    END
  END A2
  PIN A3
    DIRECTION INPUT ;
    USE SIGNAL ;
    PORT
      LAYER M1 ;
        RECT 0.102 0.064 0.118 0.08 ;
    END
  END A3
  PIN A4
    DIRECTION INPUT ;
    USE SIGNAL ;
    PORT
      LAYER M1 ;
        RECT 0.146 0.04 0.162 0.056 ;
    END
  END A4
  PIN ZN
    DIRECTION OUTPUT ;
    USE SIGNAL ;
    PORT
      LAYER M1 ;
        RECT 0.19 0.016 0.206 0.104 ;
    END
  END ZN
  OBS
    LAYER M0 DESIGNRULEWIDTH 0 ;
      RECT 0.187 0.02 0.208 0.03 ;
      RECT 0.009 0.042 0.167 0.054 ;
      RECT 0.009 0.066 0.053 0.078 ;
      RECT 0.097 0.066 0.141 0.078 ;
      RECT 0.053 0.09 0.211 0.1 ;
  END
END NAND4_X1

MACRO NOR4_X1
  CLASS CORE ;
  ORIGIN 0 0 ;
  FOREIGN NOR4_X1 0 0 ;
  SYMMETRY X Y ;
  SITE i3d_nsfet3nm ;
  SIZE 0.22 BY 0.12 ;
  PIN VSS
    DIRECTION INOUT ;
    USE GROUND ;
    PORT
      LAYER M0 ;
        RECT -0.016 -0.006 0.236 0.006 ;
    END
  END VSS
  PIN VDD
    DIRECTION INOUT ;
    USE POWER ;
    PORT
      LAYER M0 ;
        RECT -0.016 0.114 0.236 0.126 ;
    END
  END VDD
  PIN A1
    DIRECTION INPUT ;
    USE SIGNAL ;
    PORT
      LAYER M1 ;
        RECT 0.014 0.064 0.03 0.08 ;
    END
  END A1
  PIN A2
    DIRECTION INPUT ;
    USE SIGNAL ;
    PORT
      LAYER M1 ;
        RECT 0.058 0.04 0.074 0.056 ;
    END
  END A2
  PIN A3
    DIRECTION INPUT ;
    USE SIGNAL ;
    PORT
      LAYER M1 ;
        RECT 0.102 0.064 0.118 0.08 ;
    END
  END A3
  PIN A4
    DIRECTION INPUT ;
    USE SIGNAL ;
    PORT
      LAYER M1 ;
        RECT 0.146 0.04 0.162 0.056 ;
    END
  END A4
  PIN ZN
    DIRECTION OUTPUT ;
    USE SIGNAL ;
    PORT
      LAYER M1 ;
        RECT 0.19 0.016 0.206 0.104 ;
    END
  END ZN
  OBS
    LAYER M0 DESIGNRULEWIDTH 0 ;
      RECT 0.009 0.02 0.21 0.03 ;
      RECT 0.009 0.042 0.167 0.054 ;
      RECT 0.009 0.066 0.054 0.078 ;
      RECT 0.097 0.066 0.142 0.078 ;
      RECT 0.009 0.09 0.209 0.1 ;
  END
END NOR4_X1

MACRO AND2_X1
  CLASS CORE ;
  ORIGIN 0 0 ;
  FOREIGN AND2_X1 0 0 ;
  SYMMETRY X Y ;
  SITE i3d_nsfet3nm ;
  SIZE 0.22 BY 0.12 ;
  PIN A1
    DIRECTION INPUT ;
    USE SIGNAL ;
    PORT
      LAYER M1 ;
        RECT 0.014 0.016 0.03 0.104 ;
    END
  END A1
  PIN A2
    DIRECTION INPUT ;
    USE SIGNAL ;
    PORT
      LAYER M1 ;
        RECT 0.058 0.016 0.074 0.104 ;
    END
  END A2
  PIN VDD
    DIRECTION INOUT ;
    USE POWER ;
    PORT
      LAYER M0 ;
        RECT -0.016 0.114 0.236 0.126 ;
    END
  END VDD
  PIN VSS
    DIRECTION INOUT ;
    USE GROUND ;
    PORT
      LAYER M0 ;
        RECT -0.016 -0.006 0.236 0.006 ;
    END
  END VSS
  PIN ZN
    DIRECTION OUTPUT ;
    USE SIGNAL ;
    PORT
      LAYER M1 ;
        RECT 0.19 0.016 0.206 0.104 ;
    END
  END ZN
  OBS
    LAYER M1 DESIGNRULEWIDTH 0 ;
      RECT 0.102 0.016 0.118 0.104 ;
    LAYER M0 DESIGNRULEWIDTH 0 ;
      RECT 0.141 0.02 0.211 0.03 ;
      RECT 0.009 0.02 0.123 0.03 ;
      RECT 0.104 0.042 0.179 0.054 ;
      RECT 0.009 0.042 0.091 0.054 ;
      RECT 0.141 0.066 0.211 0.078 ;
      RECT 0.009 0.066 0.123 0.078 ;
      RECT 0.141 0.09 0.211 0.1 ;
      RECT 0.009 0.09 0.123 0.1 ;
  END
END AND2_X1

MACRO AND2_X2
  CLASS CORE ;
  ORIGIN 0 0 ;
  FOREIGN AND2_X2 0 0 ;
  SYMMETRY X Y ;
  SITE i3d_nsfet3nm ;
  SIZE 0.352 BY 0.12 ;
  PIN A1
    DIRECTION INPUT ;
    USE SIGNAL ;
    PORT
      LAYER M1 ;
        RECT 0.014 0.064 0.03 0.08 ;
    END
  END A1
  PIN A2
    DIRECTION INPUT ;
    USE SIGNAL ;
    PORT
      LAYER M1 ;
        RECT 0.102 0.064 0.118 0.08 ;
    END
  END A2
  PIN ZN
    DIRECTION OUTPUT ;
    USE SIGNAL ;
    PORT
      LAYER M1 ;
        RECT 0.322 0.016 0.338 0.104 ;
    END
  END ZN
  PIN VDD
    DIRECTION INOUT ;
    USE POWER ;
    PORT
      LAYER M0 ;
        RECT -0.016 0.114 0.368 0.126 ;
    END
  END VDD
  PIN VSS
    DIRECTION INOUT ;
    USE GROUND ;
    PORT
      LAYER M0 ;
        RECT -0.016 -0.006 0.368 0.006 ;
    END
  END VSS
  OBS
    LAYER M1 ;
      RECT 0.19 0.016 0.206 0.056 ;
      RECT 0.146 0.016 0.162 0.104 ;
      RECT 0.102 0.016 0.118 0.044 ;
      RECT 0.014 0.016 0.03 0.044 ;
      RECT 0.19 0.066 0.206 0.104 ;
    LAYER M0 DESIGNRULEWIDTH 0 ;
      RECT 0.229 0.02 0.343 0.03 ;
      RECT 0.187 0.02 0.211 0.03 ;
      RECT 0.142 0.02 0.166 0.03 ;
      RECT 0.098 0.02 0.122 0.03 ;
      RECT 0.011 0.02 0.035 0.03 ;
      RECT 0.009 0.042 0.212 0.054 ;
      RECT 0.192 0.066 0.311 0.078 ;
      RECT 0.104 0.066 0.179 0.078 ;
      RECT 0.011 0.066 0.091 0.078 ;
      RECT 0.229 0.09 0.343 0.1 ;
      RECT 0.054 0.09 0.211 0.1 ;
  END
END AND2_X2

MACRO AND2_X4
  CLASS CORE ;
  ORIGIN 0 0 ;
  FOREIGN AND2_X4 0 0 ;
  SYMMETRY X Y ;
  SITE i3d_nsfet3nm ;
  SIZE 0.616 BY 0.12 ;
  PIN A1
    DIRECTION INPUT ;
    USE SIGNAL ;
    PORT
      LAYER M1 ;
        RECT 0.014 0.064 0.03 0.08 ;
    END
  END A1
  PIN A2
    DIRECTION INPUT ;
    USE SIGNAL ;
    PORT
      LAYER M1 ;
        RECT 0.19 0.064 0.206 0.08 ;
    END
  END A2
  PIN ZN
    DIRECTION OUTPUT ;
    USE SIGNAL ;
    PORT
      LAYER M1 ;
        RECT 0.498 0.016 0.514 0.104 ;
    END
  END ZN
  PIN VDD
    DIRECTION INOUT ;
    USE POWER ;
    PORT
      LAYER M0 ;
        RECT -0.016 0.114 0.632 0.126 ;
    END
  END VDD
  PIN VSS
    DIRECTION INOUT ;
    USE GROUND ;
    PORT
      LAYER M0 ;
        RECT -0.016 -0.006 0.632 0.006 ;
    END
  END VSS
  OBS
    LAYER M1 DESIGNRULEWIDTH 0 ;
      RECT 0.586 0.016 0.602 0.104 ;
      RECT 0.542 0.016 0.558 0.104 ;
      RECT 0.454 0.016 0.47 0.104 ;
      RECT 0.41 0.016 0.426 0.104 ;
      RECT 0.322 0.016 0.338 0.104 ;
      RECT 0.366 0.064 0.382 0.104 ;
    LAYER M0 DESIGNRULEWIDTH 0 ;
      RECT 0.405 0.02 0.606 0.03 ;
      RECT 0.23 0.02 0.342 0.03 ;
      RECT 0.405 0.042 0.606 0.054 ;
      RECT 0.009 0.042 0.384 0.054 ;
      RECT 0.368 0.066 0.606 0.078 ;
      RECT 0.192 0.066 0.355 0.078 ;
      RECT 0.011 0.066 0.179 0.078 ;
      RECT 0.405 0.09 0.606 0.1 ;
      RECT 0.054 0.09 0.387 0.1 ;
  END
END AND2_X4

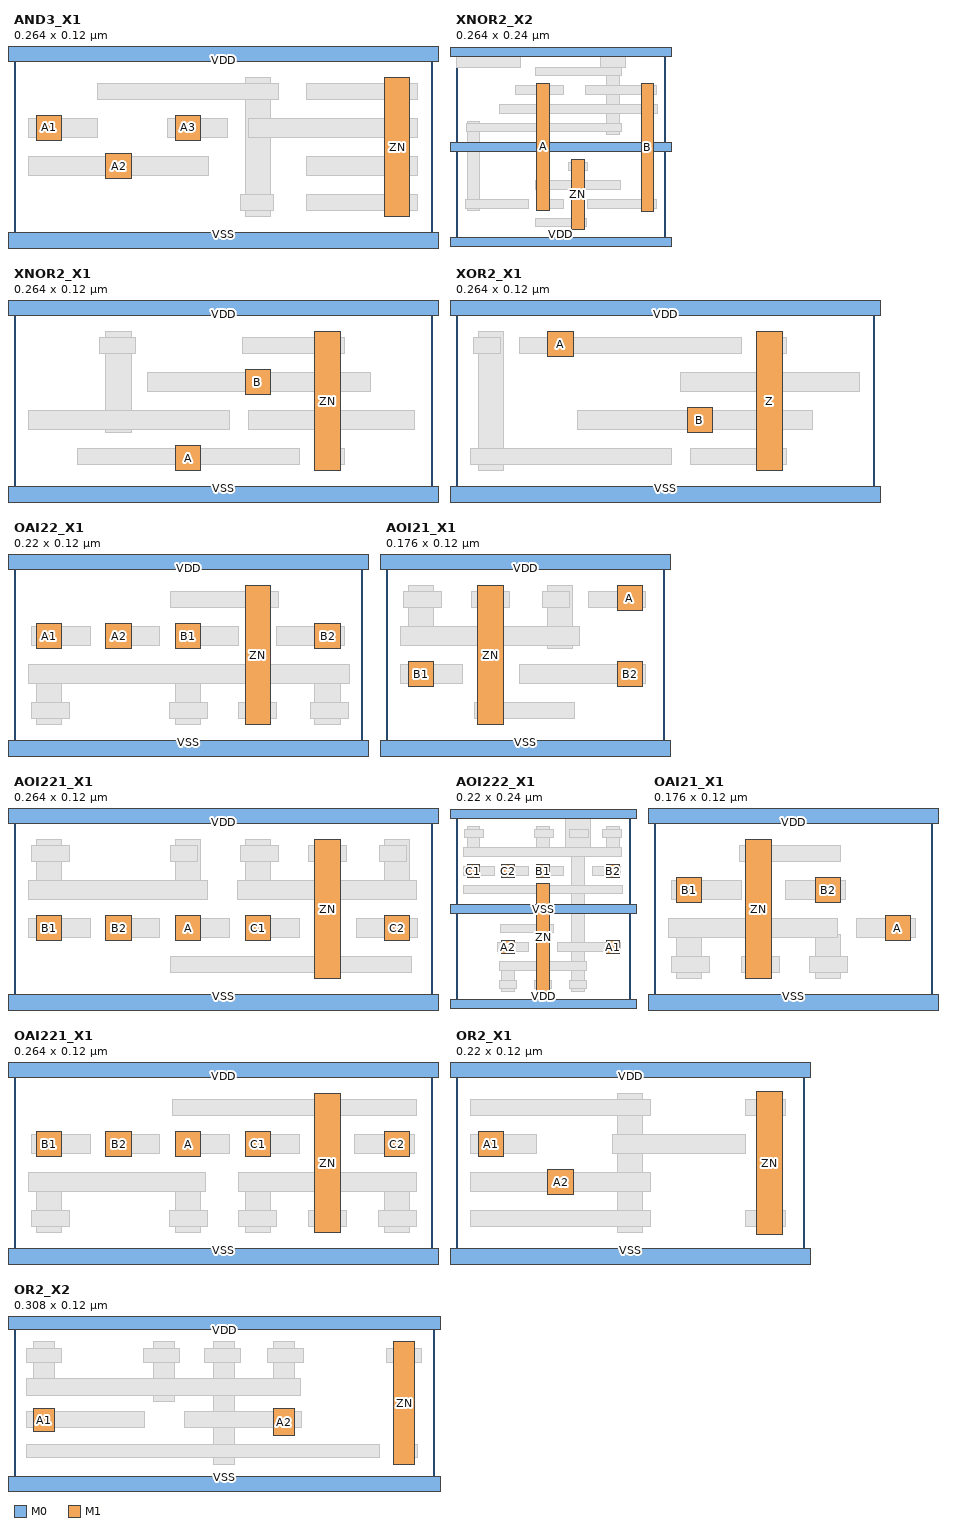
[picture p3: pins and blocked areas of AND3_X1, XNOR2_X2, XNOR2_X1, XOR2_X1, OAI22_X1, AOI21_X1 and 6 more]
MACRO AND3_X1
  CLASS CORE ;
  ORIGIN 0 0 ;
  FOREIGN AND3_X1 0 0 ;
  SYMMETRY X Y ;
  SITE i3d_nsfet3nm ;
  SIZE 0.264 BY 0.12 ;
  PIN VDD
    DIRECTION INOUT ;
    USE POWER ;
    PORT
      LAYER M0 ;
        RECT -0.016 0.114 0.28 0.126 ;
    END
  END VDD
  PIN VSS
    DIRECTION INOUT ;
    USE GROUND ;
    PORT
      LAYER M0 ;
        RECT -0.016 -0.006 0.28 0.006 ;
    END
  END VSS
  PIN A1
    DIRECTION INPUT ;
    USE SIGNAL ;
    PORT
      LAYER M1 ;
        RECT 0.014 0.064 0.03 0.08 ;
    END
  END A1
  PIN A2
    DIRECTION INPUT ;
    USE SIGNAL ;
    PORT
      LAYER M1 ;
        RECT 0.058 0.04 0.074 0.056 ;
    END
  END A2
  PIN A3
    DIRECTION INPUT ;
    USE SIGNAL ;
    PORT
      LAYER M1 ;
        RECT 0.102 0.064 0.118 0.08 ;
    END
  END A3
  PIN ZN
    DIRECTION OUTPUT ;
    USE SIGNAL ;
    PORT
      LAYER M1 ;
        RECT 0.234 0.016 0.25 0.104 ;
    END
  END ZN
  OBS
    LAYER M1 DESIGNRULEWIDTH 0 ;
      RECT 0.146 0.016 0.162 0.104 ;
    LAYER M0 DESIGNRULEWIDTH 0 ;
      RECT 0.185 0.02 0.255 0.03 ;
      RECT 0.143 0.02 0.164 0.03 ;
      RECT 0.185 0.042 0.255 0.054 ;
      RECT 0.009 0.042 0.123 0.054 ;
      RECT 0.148 0.066 0.255 0.078 ;
      RECT 0.097 0.066 0.135 0.078 ;
      RECT 0.009 0.066 0.053 0.078 ;
      RECT 0.185 0.09 0.255 0.1 ;
      RECT 0.053 0.09 0.167 0.1 ;
  END
END AND3_X1

MACRO XNOR2_X2
  CLASS CORE ;
  ORIGIN 0 0 ;
  FOREIGN XNOR2X2 0 0 ;
  SYMMETRY X Y ;
  SITE i3d_nsfet3nm ;
  SIZE 0.264 BY 0.24 ;
  PIN VDD
    DIRECTION INOUT ;
    USE POWER ;
    PORT
      LAYER M0 ;
        RECT -0.016 -0.006 0.28 0.006 ;
        RECT -0.016 0.234 0.28 0.246 ;
    END
  END VDD
  PIN VSS
    DIRECTION INOUT ;
    USE GROUND ;
    PORT
      LAYER M0 ;
        RECT -0.016 0.114 0.28 0.126 ;
    END
  END VSS
  PIN A
    DIRECTION INPUT ;
    USE SIGNAL ;
    PORT
      LAYER M1 ;
        RECT 0.102 0.04 0.118 0.2 ;
    END
  END A
  PIN B
    DIRECTION INPUT ;
    USE SIGNAL ;
    PORT
      LAYER M1 ;
        RECT 0.234 0.038 0.25 0.2 ;
    END
  END B
  PIN ZN
    DIRECTION OUTPUT ;
    USE SIGNAL ;
    PORT
      LAYER M1 ;
        RECT 0.146 0.016 0.162 0.104 ;
    END
  END ZN
  OBS
    LAYER M1 DESIGNRULEWIDTH 0 ;
      RECT 0.014 0.04 0.03 0.152 ;
      POLYGON 0.206 0.136 0.206 0.22 0.214 0.22 0.214 0.24 0.182 0.24 0.182 0.22 0.19 0.22 0.19 0.136 ;
      RECT 0 0.22 0.082 0.24 ;
    LAYER M0 DESIGNRULEWIDTH 0 ;
      RECT 0.1 0.02 0.165 0.03 ;
      RECT 0.166 0.042 0.253 0.054 ;
      RECT 0.104 0.042 0.136 0.054 ;
      RECT 0.012 0.042 0.092 0.054 ;
      RECT 0.1 0.066 0.208 0.078 ;
      RECT 0.142 0.09 0.166 0.1 ;
      RECT 0.013 0.14 0.209 0.15 ;
      RECT 0.055 0.162 0.254 0.174 ;
      RECT 0.163 0.186 0.253 0.198 ;
      RECT 0.075 0.186 0.136 0.198 ;
      RECT 0.1 0.21 0.209 0.22 ;
  END
END XNOR2_X2

MACRO XNOR2_X1
  CLASS CORE ;
  ORIGIN 0 0 ;
  FOREIGN XNOR2_X1 0 0 ;
  SYMMETRY X Y ;
  SITE i3d_nsfet3nm ;
  SIZE 0.264 BY 0.12 ;
  PIN VDD
    DIRECTION INOUT ;
    USE POWER ;
    PORT
      LAYER M0 ;
        RECT -0.016 0.114 0.28 0.126 ;
    END
  END VDD
  PIN VSS
    DIRECTION INOUT ;
    USE GROUND ;
    PORT
      LAYER M0 ;
        RECT -0.016 -0.006 0.28 0.006 ;
    END
  END VSS
  PIN A
    DIRECTION INPUT ;
    USE SIGNAL ;
    PORT
      LAYER M1 ;
        RECT 0.102 0.016 0.118 0.032 ;
    END
  END A
  PIN B
    DIRECTION INPUT ;
    USE SIGNAL ;
    PORT
      LAYER M1 ;
        RECT 0.146 0.064 0.162 0.08 ;
    END
  END B
  PIN ZN
    DIRECTION OUTPUT ;
    USE SIGNAL ;
    PORT
      LAYER M1 ;
        RECT 0.19 0.016 0.206 0.104 ;
    END
  END ZN
  OBS
    LAYER M1 DESIGNRULEWIDTH 0 ;
      RECT 0.058 0.04 0.074 0.104 ;
    LAYER M0 DESIGNRULEWIDTH 0 ;
      RECT 0.192 0.02 0.209 0.03 ;
      RECT 0.04 0.02 0.18 0.03 ;
      RECT 0.148 0.042 0.253 0.054 ;
      RECT 0.009 0.042 0.136 0.054 ;
      RECT 0.084 0.066 0.225 0.078 ;
      RECT 0.144 0.09 0.209 0.1 ;
      RECT 0.054 0.09 0.077 0.1 ;
  END
END XNOR2_X1

MACRO XOR2_X1
  CLASS CORE ;
  ORIGIN 0 0 ;
  FOREIGN XOR2_X1 0 0 ;
  SYMMETRY X Y ;
  SITE i3d_nsfet3nm ;
  SIZE 0.264 BY 0.12 ;
  PIN VDD
    DIRECTION INOUT ;
    USE POWER ;
    PORT
      LAYER M0 ;
        RECT -0.016 0.114 0.28 0.126 ;
    END
  END VDD
  PIN VSS
    DIRECTION INOUT ;
    USE GROUND ;
    PORT
      LAYER M0 ;
        RECT -0.016 -0.006 0.28 0.006 ;
    END
  END VSS
  PIN A
    DIRECTION INPUT ;
    USE SIGNAL ;
    PORT
      LAYER M1 ;
        RECT 0.058 0.088 0.074 0.104 ;
    END
  END A
  PIN B
    DIRECTION INPUT ;
    USE SIGNAL ;
    PORT
      LAYER M1 ;
        RECT 0.146 0.04 0.162 0.056 ;
    END
  END B
  PIN Z
    DIRECTION OUTPUT ;
    USE SIGNAL ;
    PORT
      LAYER M1 ;
        RECT 0.19 0.016 0.206 0.104 ;
    END
  END Z
  OBS
    LAYER M1 DESIGNRULEWIDTH 0 ;
      RECT 0.014 0.016 0.03 0.104 ;
    LAYER M0 DESIGNRULEWIDTH 0 ;
      RECT 0.148 0.02 0.209 0.03 ;
      RECT 0.009 0.02 0.136 0.03 ;
      RECT 0.077 0.042 0.225 0.054 ;
      RECT 0.142 0.066 0.255 0.078 ;
      RECT 0.192 0.09 0.209 0.1 ;
      RECT 0.04 0.09 0.18 0.1 ;
      RECT 0.011 0.09 0.028 0.1 ;
  END
END XOR2_X1

MACRO OAI22_X1
  CLASS CORE ;
  ORIGIN 0 0 ;
  FOREIGN OAI22_X1 0 0 ;
  SYMMETRY X Y ;
  SITE i3d_nsfet3nm ;
  SIZE 0.22 BY 0.12 ;
  PIN VDD
    DIRECTION INOUT ;
    USE POWER ;
    PORT
      LAYER M0 ;
        RECT -0.016 0.114 0.236 0.126 ;
    END
  END VDD
  PIN A1
    DIRECTION INPUT ;
    USE SIGNAL ;
    PORT
      LAYER M1 ;
        RECT 0.014 0.064 0.03 0.08 ;
    END
  END A1
  PIN A2
    DIRECTION INPUT ;
    USE SIGNAL ;
    PORT
      LAYER M1 ;
        RECT 0.058 0.064 0.074 0.08 ;
    END
  END A2
  PIN B1
    DIRECTION INPUT ;
    USE SIGNAL ;
    PORT
      LAYER M1 ;
        RECT 0.102 0.064 0.118 0.08 ;
    END
  END B1
  PIN ZN
    DIRECTION OUTPUT ;
    USE SIGNAL ;
    PORT
      LAYER M1 ;
        RECT 0.146 0.016 0.162 0.104 ;
    END
  END ZN
  PIN B2
    DIRECTION INPUT ;
    USE SIGNAL ;
    PORT
      LAYER M1 ;
        RECT 0.19 0.064 0.206 0.08 ;
    END
  END B2
  PIN VSS
    DIRECTION INOUT ;
    USE GROUND ;
    PORT
      LAYER M0 ;
        RECT -0.016 -0.006 0.236 0.006 ;
    END
  END VSS
  OBS
    LAYER M1 DESIGNRULEWIDTH 0 ;
      RECT 0.19 0.016 0.206 0.044 ;
      RECT 0.102 0.016 0.118 0.044 ;
      RECT 0.014 0.016 0.03 0.044 ;
    LAYER M0 DESIGNRULEWIDTH 0 ;
      RECT 0.187 0.02 0.211 0.03 ;
      RECT 0.142 0.02 0.166 0.03 ;
      RECT 0.098 0.02 0.122 0.03 ;
      RECT 0.011 0.02 0.035 0.03 ;
      RECT 0.009 0.042 0.212 0.054 ;
      RECT 0.166 0.066 0.209 0.078 ;
      RECT 0.104 0.066 0.142 0.078 ;
      RECT 0.06 0.066 0.092 0.078 ;
      RECT 0.011 0.066 0.048 0.078 ;
      RECT 0.099 0.09 0.167 0.1 ;
  END
END OAI22_X1

MACRO AOI21_X1
  CLASS CORE ;
  ORIGIN 0 0 ;
  FOREIGN AOI21_X1 0 0 ;
  SYMMETRY X Y ;
  SITE i3d_nsfet3nm ;
  SIZE 0.176 BY 0.12 ;
  PIN VDD
    DIRECTION INOUT ;
    USE POWER ;
    PORT
      LAYER M0 ;
        RECT -0.016 0.114 0.192 0.126 ;
    END
  END VDD
  PIN B1
    DIRECTION INPUT ;
    USE SIGNAL ;
    PORT
      LAYER M1 ;
        RECT 0.014 0.04 0.03 0.056 ;
    END
  END B1
  PIN ZN
    DIRECTION OUTPUT ;
    USE SIGNAL ;
    PORT
      LAYER M1 ;
        RECT 0.058 0.016 0.074 0.104 ;
    END
  END ZN
  PIN A
    DIRECTION INPUT ;
    USE SIGNAL ;
    PORT
      LAYER M1 ;
        RECT 0.146 0.088 0.162 0.104 ;
    END
  END A
  PIN B2
    DIRECTION INPUT ;
    USE SIGNAL ;
    PORT
      LAYER M1 ;
        RECT 0.146 0.04 0.162 0.056 ;
    END
  END B2
  PIN VSS
    DIRECTION INOUT ;
    USE GROUND ;
    PORT
      LAYER M0 ;
        RECT -0.016 -0.006 0.192 0.006 ;
    END
  END VSS
  OBS
    LAYER M1 DESIGNRULEWIDTH 0 ;
      RECT 0.102 0.064 0.118 0.104 ;
      RECT 0.014 0.076 0.03 0.104 ;
    LAYER M0 DESIGNRULEWIDTH 0 ;
      RECT 0.056 0.02 0.119 0.03 ;
      RECT 0.084 0.042 0.164 0.054 ;
      RECT 0.009 0.042 0.048 0.054 ;
      RECT 0.009 0.066 0.122 0.078 ;
      RECT 0.128 0.09 0.164 0.1 ;
      RECT 0.099 0.09 0.116 0.1 ;
      RECT 0.054 0.09 0.078 0.1 ;
      RECT 0.011 0.09 0.035 0.1 ;
  END
END AOI21_X1

MACRO AOI221_X1
  CLASS CORE ;
  ORIGIN 0 0 ;
  FOREIGN AOI221_X1 0 0 ;
  SYMMETRY X Y ;
  SITE i3d_nsfet3nm ;
  SIZE 0.264 BY 0.12 ;
  PIN VDD
    DIRECTION INOUT ;
    USE POWER ;
    PORT
      LAYER M0 ;
        RECT -0.016 0.114 0.28 0.126 ;
    END
  END VDD
  PIN VSS
    DIRECTION INOUT ;
    USE GROUND ;
    PORT
      LAYER M0 ;
        RECT -0.016 -0.006 0.28 0.006 ;
    END
  END VSS
  PIN B1
    DIRECTION INPUT ;
    USE SIGNAL ;
    PORT
      LAYER M1 ;
        RECT 0.014 0.04 0.03 0.056 ;
    END
  END B1
  PIN B2
    DIRECTION INPUT ;
    USE SIGNAL ;
    PORT
      LAYER M1 ;
        RECT 0.058 0.04 0.074 0.056 ;
    END
  END B2
  PIN A
    DIRECTION INPUT ;
    USE SIGNAL ;
    PORT
      LAYER M1 ;
        RECT 0.102 0.04 0.118 0.056 ;
    END
  END A
  PIN C1
    DIRECTION INPUT ;
    USE SIGNAL ;
    PORT
      LAYER M1 ;
        RECT 0.146 0.04 0.162 0.056 ;
    END
  END C1
  PIN ZN
    DIRECTION OUTPUT ;
    USE SIGNAL ;
    PORT
      LAYER M1 ;
        RECT 0.19 0.016 0.206 0.104 ;
    END
  END ZN
  PIN C2
    DIRECTION INPUT ;
    USE SIGNAL ;
    PORT
      LAYER M1 ;
        RECT 0.234 0.04 0.25 0.056 ;
    END
  END C2
  OBS
    LAYER M1 DESIGNRULEWIDTH 0 ;
      RECT 0.234 0.076 0.25 0.104 ;
      RECT 0.146 0.076 0.162 0.104 ;
      RECT 0.102 0.076 0.118 0.104 ;
      RECT 0.014 0.076 0.03 0.104 ;
    LAYER M0 DESIGNRULEWIDTH 0 ;
      RECT 0.099 0.02 0.251 0.03 ;
      RECT 0.216 0.042 0.255 0.054 ;
      RECT 0.148 0.042 0.18 0.054 ;
      RECT 0.104 0.042 0.136 0.054 ;
      RECT 0.06 0.042 0.092 0.054 ;
      RECT 0.009 0.042 0.048 0.054 ;
      RECT 0.141 0.066 0.254 0.078 ;
      RECT 0.009 0.066 0.122 0.078 ;
      RECT 0.231 0.09 0.248 0.1 ;
      RECT 0.186 0.09 0.21 0.1 ;
      RECT 0.143 0.09 0.167 0.1 ;
      RECT 0.099 0.09 0.116 0.1 ;
      RECT 0.011 0.09 0.035 0.1 ;
  END
END AOI221_X1

MACRO AOI222_X1
  CLASS CORE ;
  ORIGIN 0 0 ;
  FOREIGN AOI222_X1 0 0 ;
  SYMMETRY X Y ;
  SITE i3d_nsfet3nm ;
  SIZE 0.22 BY 0.24 ;
  PIN VDD
    DIRECTION INOUT ;
    USE POWER ;
    PORT
      LAYER M0 ;
        RECT -0.016 -0.006 0.236 0.006 ;
        RECT -0.016 0.234 0.236 0.246 ;
    END
  END VDD
  PIN VSS
    DIRECTION INOUT ;
    USE GROUND ;
    PORT
      LAYER M0 ;
        RECT -0.016 0.114 0.236 0.126 ;
    END
  END VSS
  PIN C1
    DIRECTION INPUT ;
    USE SIGNAL ;
    PORT
      LAYER M1 ;
        RECT 0.014 0.16 0.03 0.176 ;
    END
  END C1
  PIN C2
    DIRECTION INPUT ;
    USE SIGNAL ;
    PORT
      LAYER M1 ;
        RECT 0.058 0.16 0.074 0.176 ;
    END
  END C2
  PIN B1
    DIRECTION INPUT ;
    USE SIGNAL ;
    PORT
      LAYER M1 ;
        RECT 0.102 0.16 0.118 0.176 ;
    END
  END B1
  PIN B2
    DIRECTION INPUT ;
    USE SIGNAL ;
    PORT
      LAYER M1 ;
        RECT 0.19 0.16 0.206 0.176 ;
    END
  END B2
  PIN A2
    DIRECTION INPUT ;
    USE SIGNAL ;
    PORT
      LAYER M1 ;
        RECT 0.058 0.064 0.074 0.08 ;
    END
  END A2
  PIN A1
    DIRECTION INPUT ;
    USE SIGNAL ;
    PORT
      LAYER M1 ;
        RECT 0.19 0.064 0.206 0.08 ;
    END
  END A1
  PIN ZN
    DIRECTION OUTPUT ;
    USE SIGNAL ;
    PORT
      LAYER M1 ;
        RECT 0.102 0.016 0.118 0.152 ;
    END
  END ZN
  OBS
    LAYER M1 DESIGNRULEWIDTH 0 ;
      POLYGON 0.162 0.016 0.162 0.196 0.17 0.196 0.17 0.24 0.138 0.24 0.138 0.196 0.146 0.196 0.146 0.016 ;
      RECT 0.058 0.016 0.074 0.044 ;
      RECT 0.19 0.196 0.206 0.224 ;
      RECT 0.102 0.196 0.118 0.224 ;
      RECT 0.014 0.196 0.03 0.224 ;
    LAYER M0 DESIGNRULEWIDTH 0 ;
      RECT 0.143 0.02 0.165 0.03 ;
      RECT 0.099 0.02 0.121 0.03 ;
      RECT 0.055 0.02 0.077 0.03 ;
      RECT 0.055 0.042 0.165 0.054 ;
      RECT 0.128 0.066 0.208 0.078 ;
      RECT 0.053 0.066 0.092 0.078 ;
      RECT 0.056 0.09 0.123 0.1 ;
      RECT 0.009 0.14 0.21 0.15 ;
      RECT 0.172 0.162 0.208 0.174 ;
      RECT 0.104 0.162 0.136 0.174 ;
      RECT 0.06 0.162 0.092 0.174 ;
      RECT 0.009 0.162 0.048 0.174 ;
      RECT 0.009 0.186 0.209 0.198 ;
      RECT 0.185 0.21 0.209 0.22 ;
      RECT 0.143 0.21 0.167 0.22 ;
      RECT 0.099 0.21 0.123 0.22 ;
      RECT 0.011 0.21 0.035 0.22 ;
  END
END AOI222_X1

MACRO OAI21_X1
  CLASS CORE ;
  ORIGIN 0 0 ;
  FOREIGN OAI21_X1 0 0 ;
  SYMMETRY X Y ;
  SITE i3d_nsfet3nm ;
  SIZE 0.176 BY 0.12 ;
  PIN VDD
    DIRECTION INOUT ;
    USE POWER ;
    PORT
      LAYER M0 ;
        RECT -0.016 0.114 0.192 0.126 ;
    END
  END VDD
  PIN VSS
    DIRECTION INOUT ;
    USE GROUND ;
    PORT
      LAYER M0 ;
        RECT -0.016 -0.006 0.192 0.006 ;
    END
  END VSS
  PIN B1
    DIRECTION INPUT ;
    USE SIGNAL ;
    PORT
      LAYER M1 ;
        RECT 0.014 0.064 0.03 0.08 ;
    END
  END B1
  PIN ZN
    DIRECTION OUTPUT ;
    USE SIGNAL ;
    PORT
      LAYER M1 ;
        RECT 0.058 0.016 0.074 0.104 ;
    END
  END ZN
  PIN B2
    DIRECTION INPUT ;
    USE SIGNAL ;
    PORT
      LAYER M1 ;
        RECT 0.102 0.064 0.118 0.08 ;
    END
  END B2
  PIN A
    DIRECTION INPUT ;
    USE SIGNAL ;
    PORT
      LAYER M1 ;
        RECT 0.146 0.04 0.162 0.056 ;
    END
  END A
  OBS
    LAYER M1 DESIGNRULEWIDTH 0 ;
      RECT 0.102 0.016 0.118 0.044 ;
      RECT 0.014 0.016 0.03 0.044 ;
    LAYER M0 DESIGNRULEWIDTH 0 ;
      RECT 0.098 0.02 0.122 0.03 ;
      RECT 0.055 0.02 0.079 0.03 ;
      RECT 0.011 0.02 0.035 0.03 ;
      RECT 0.128 0.042 0.165 0.054 ;
      RECT 0.009 0.042 0.116 0.054 ;
      RECT 0.083 0.066 0.121 0.078 ;
      RECT 0.011 0.066 0.055 0.078 ;
      RECT 0.054 0.09 0.118 0.1 ;
  END
END OAI21_X1

MACRO OAI221_X1
  CLASS CORE ;
  ORIGIN 0 0 ;
  FOREIGN OAI221_X1 0 0 ;
  SYMMETRY X Y ;
  SITE i3d_nsfet3nm ;
  SIZE 0.264 BY 0.12 ;
  PIN VDD
    DIRECTION INOUT ;
    USE POWER ;
    PORT
      LAYER M0 ;
        RECT -0.016 0.114 0.28 0.126 ;
    END
  END VDD
  PIN VSS
    DIRECTION INOUT ;
    USE GROUND ;
    PORT
      LAYER M0 ;
        RECT -0.016 -0.006 0.28 0.006 ;
    END
  END VSS
  PIN B1
    DIRECTION INPUT ;
    USE SIGNAL ;
    PORT
      LAYER M1 ;
        RECT 0.014 0.064 0.03 0.08 ;
    END
  END B1
  PIN B2
    DIRECTION INPUT ;
    USE SIGNAL ;
    PORT
      LAYER M1 ;
        RECT 0.058 0.064 0.074 0.08 ;
    END
  END B2
  PIN A
    DIRECTION INPUT ;
    USE SIGNAL ;
    PORT
      LAYER M1 ;
        RECT 0.102 0.064 0.118 0.08 ;
    END
  END A
  PIN C1
    DIRECTION INPUT ;
    USE SIGNAL ;
    PORT
      LAYER M1 ;
        RECT 0.146 0.064 0.162 0.08 ;
    END
  END C1
  PIN ZN
    DIRECTION OUTPUT ;
    USE SIGNAL ;
    PORT
      LAYER M1 ;
        RECT 0.19 0.016 0.206 0.104 ;
    END
  END ZN
  PIN C2
    DIRECTION INPUT ;
    USE SIGNAL ;
    PORT
      LAYER M1 ;
        RECT 0.234 0.064 0.25 0.08 ;
    END
  END C2
  OBS
    LAYER M1 DESIGNRULEWIDTH 0 ;
      RECT 0.234 0.016 0.25 0.044 ;
      RECT 0.146 0.016 0.162 0.044 ;
      RECT 0.102 0.016 0.118 0.044 ;
      RECT 0.014 0.016 0.03 0.044 ;
    LAYER M0 DESIGNRULEWIDTH 0 ;
      RECT 0.23 0.02 0.254 0.03 ;
      RECT 0.186 0.02 0.21 0.03 ;
      RECT 0.142 0.02 0.166 0.03 ;
      RECT 0.098 0.02 0.122 0.03 ;
      RECT 0.011 0.02 0.035 0.03 ;
      RECT 0.142 0.042 0.254 0.054 ;
      RECT 0.009 0.042 0.121 0.054 ;
      RECT 0.215 0.066 0.253 0.078 ;
      RECT 0.148 0.066 0.18 0.078 ;
      RECT 0.104 0.066 0.136 0.078 ;
      RECT 0.06 0.066 0.092 0.078 ;
      RECT 0.011 0.066 0.048 0.078 ;
      RECT 0.1 0.09 0.254 0.1 ;
  END
END OAI221_X1

MACRO OR2_X1
  CLASS CORE ;
  ORIGIN 0 0 ;
  FOREIGN OR2_X1 0 0 ;
  SYMMETRY X Y ;
  SITE i3d_nsfet3nm ;
  SIZE 0.22 BY 0.12 ;
  PIN VDD
    DIRECTION INOUT ;
    USE POWER ;
    PORT
      LAYER M0 ;
        RECT -0.016 0.114 0.236 0.126 ;
    END
  END VDD
  PIN VSS
    DIRECTION INOUT ;
    USE GROUND ;
    PORT
      LAYER M0 ;
        RECT -0.016 -0.006 0.236 0.006 ;
    END
  END VSS
  PIN A1
    DIRECTION INPUT ;
    USE SIGNAL ;
    PORT
      LAYER M1 ;
        RECT 0.014 0.064 0.03 0.08 ;
    END
  END A1
  PIN ZN
    DIRECTION OUTPUT ;
    USE SIGNAL ;
    PORT
      LAYER M1 ;
        RECT 0.19 0.015 0.206 0.105 ;
    END
  END ZN
  PIN A2
    DIRECTION INPUT ;
    USE SIGNAL ;
    PORT
      LAYER M1 ;
        RECT 0.058 0.04 0.074 0.056 ;
    END
  END A2
  OBS
    LAYER M1 DESIGNRULEWIDTH 0 ;
      RECT 0.102 0.016 0.118 0.104 ;
    LAYER M0 DESIGNRULEWIDTH 0 ;
      RECT 0.183 0.02 0.208 0.03 ;
      RECT 0.009 0.02 0.123 0.03 ;
      RECT 0.009 0.042 0.123 0.054 ;
      RECT 0.099 0.066 0.183 0.078 ;
      RECT 0.009 0.066 0.051 0.078 ;
      RECT 0.183 0.09 0.208 0.1 ;
      RECT 0.009 0.09 0.123 0.1 ;
  END
END OR2_X1

MACRO OR2_X2
  CLASS CORE ;
  ORIGIN 0 0 ;
  FOREIGN OR2_X2 0 0 ;
  SYMMETRY X Y ;
  SITE i3d_nsfet3nm ;
  SIZE 0.308 BY 0.12 ;
  PIN VDD
    DIRECTION INOUT ;
    USE POWER ;
    PORT
      LAYER M0 ;
        RECT -0.016 0.114 0.324 0.126 ;
    END
  END VDD
  PIN VSS
    DIRECTION INOUT ;
    USE GROUND ;
    PORT
      LAYER M0 ;
        RECT -0.016 -0.006 0.324 0.006 ;
    END
  END VSS
  PIN A1
    DIRECTION INPUT ;
    USE SIGNAL ;
    PORT
      LAYER M1 ;
        RECT 0.014 0.039 0.03 0.056 ;
    END
  END A1
  PIN A2
    DIRECTION INPUT ;
    USE SIGNAL ;
    PORT
      LAYER M1 ;
        RECT 0.19 0.036 0.206 0.056 ;
    END
  END A2
  PIN ZN
    DIRECTION OUTPUT ;
    USE SIGNAL ;
    PORT
      LAYER M1 ;
        RECT 0.278 0.015 0.294 0.105 ;
    END
  END ZN
  OBS
    LAYER M1 DESIGNRULEWIDTH 0 ;
      RECT 0.146 0.015 0.162 0.105 ;
      RECT 0.102 0.061 0.118 0.105 ;
      RECT 0.19 0.076 0.206 0.105 ;
      RECT 0.014 0.076 0.03 0.105 ;
    LAYER M0 DESIGNRULEWIDTH 0 ;
      RECT 0.28 0.02 0.296 0.03 ;
      RECT 0.009 0.02 0.268 0.03 ;
      RECT 0.125 0.042 0.211 0.054 ;
      RECT 0.009 0.042 0.096 0.054 ;
      RECT 0.009 0.066 0.21 0.078 ;
      RECT 0.273 0.09 0.299 0.1 ;
      RECT 0.186 0.09 0.212 0.1 ;
      RECT 0.14 0.09 0.166 0.1 ;
      RECT 0.095 0.09 0.121 0.1 ;
      RECT 0.009 0.09 0.035 0.1 ;
  END
END OR2_X2

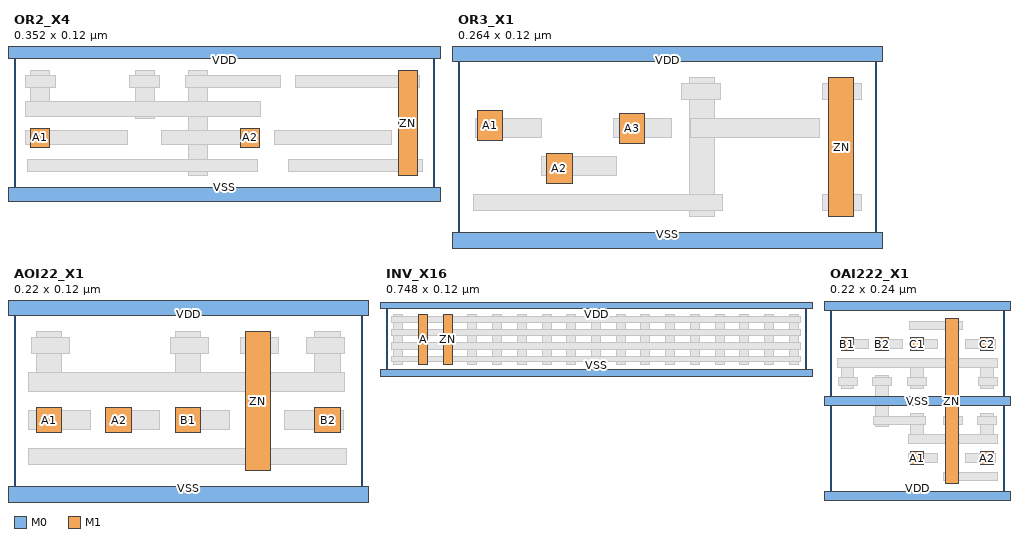
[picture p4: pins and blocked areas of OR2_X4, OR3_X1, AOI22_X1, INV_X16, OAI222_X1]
MACRO OR2_X4
  CLASS CORE ;
  ORIGIN 0 0 ;
  FOREIGN OR2_X4 0 0 ;
  SYMMETRY X Y ;
  SITE i3d_nsfet3nm ;
  SIZE 0.352 BY 0.12 ;
  PIN VDD
    DIRECTION INOUT ;
    USE POWER ;
    PORT
      LAYER M0 ;
        RECT -0.016 0.114 0.368 0.126 ;
    END
  END VDD
  PIN VSS
    DIRECTION INOUT ;
    USE GROUND ;
    PORT
      LAYER M0 ;
        RECT -0.016 -0.006 0.368 0.006 ;
    END
  END VSS
  PIN A1
    DIRECTION INPUT ;
    USE SIGNAL ;
    PORT
      LAYER M1 ;
        RECT 0.014 0.04 0.03 0.056 ;
    END
  END A1
  PIN A2
    DIRECTION INPUT ;
    USE SIGNAL ;
    PORT
      LAYER M1 ;
        RECT 0.19 0.04 0.206 0.056 ;
    END
  END A2
  PIN ZN
    DIRECTION OUTPUT ;
    USE SIGNAL ;
    PORT
      LAYER M1 ;
        RECT 0.322 0.016 0.338 0.104 ;
    END
  END ZN
  OBS
    LAYER M1 DESIGNRULEWIDTH 0 ;
      RECT 0.146 0.016 0.162 0.104 ;
      RECT 0.102 0.064 0.118 0.104 ;
      RECT 0.014 0.076 0.03 0.104 ;
    LAYER M0 DESIGNRULEWIDTH 0 ;
      RECT 0.23 0.02 0.342 0.03 ;
      RECT 0.011 0.02 0.204 0.03 ;
      RECT 0.218 0.042 0.316 0.054 ;
      RECT 0.124 0.042 0.205 0.054 ;
      RECT 0.01 0.042 0.095 0.054 ;
      RECT 0.01 0.066 0.207 0.078 ;
      RECT 0.236 0.09 0.34 0.1 ;
      RECT 0.144 0.09 0.223 0.1 ;
      RECT 0.097 0.09 0.122 0.1 ;
      RECT 0.01 0.09 0.035 0.1 ;
  END
END OR2_X4

MACRO OR3_X1
  CLASS CORE ;
  ORIGIN 0 0 ;
  FOREIGN OR3_X1 0 0 ;
  SYMMETRY X Y ;
  SITE i3d_nsfet3nm ;
  SIZE 0.264 BY 0.12 ;
  PIN VDD
    DIRECTION INOUT ;
    USE POWER ;
    PORT
      LAYER M0 ;
        RECT -0.016 0.114 0.28 0.126 ;
    END
  END VDD
  PIN VSS
    DIRECTION INOUT ;
    USE GROUND ;
    PORT
      LAYER M0 ;
        RECT -0.016 -0.006 0.28 0.006 ;
    END
  END VSS
  PIN A1
    DIRECTION INPUT ;
    USE SIGNAL ;
    PORT
      LAYER M1 ;
        RECT 0.012 0.064 0.028 0.083 ;
    END
  END A1
  PIN A2
    DIRECTION INPUT ;
    USE SIGNAL ;
    PORT
      LAYER M1 ;
        RECT 0.056 0.037 0.072 0.056 ;
    END
  END A2
  PIN A3
    DIRECTION INPUT ;
    USE SIGNAL ;
    PORT
      LAYER M1 ;
        RECT 0.102 0.062 0.118 0.081 ;
    END
  END A3
  PIN ZN
    DIRECTION OUTPUT ;
    USE SIGNAL ;
    PORT
      LAYER M1 ;
        RECT 0.234 0.016 0.25 0.104 ;
    END
  END ZN
  OBS
    LAYER M1 DESIGNRULEWIDTH 0 ;
      RECT 0.146 0.016 0.162 0.104 ;
    LAYER M0 DESIGNRULEWIDTH 0 ;
      RECT 0.23 0.02 0.255 0.03 ;
      RECT 0.01 0.02 0.167 0.03 ;
      RECT 0.053 0.042 0.1 0.054 ;
      RECT 0.147 0.066 0.228 0.078 ;
      RECT 0.098 0.066 0.135 0.078 ;
      RECT 0.011 0.066 0.053 0.078 ;
      RECT 0.23 0.09 0.255 0.1 ;
      RECT 0.141 0.09 0.166 0.1 ;
  END
END OR3_X1

MACRO AOI22_X1
  CLASS CORE ;
  ORIGIN 0 0 ;
  FOREIGN AOI22_X1 0 0 ;
  SYMMETRY X Y ;
  SITE i3d_nsfet3nm ;
  SIZE 0.22 BY 0.12 ;
  PIN VDD
    DIRECTION INOUT ;
    USE POWER ;
    PORT
      LAYER M0 ;
        RECT -0.016 0.114 0.236 0.126 ;
    END
  END VDD
  PIN VSS
    DIRECTION INOUT ;
    USE GROUND ;
    PORT
      LAYER M0 ;
        RECT -0.016 -0.006 0.236 0.006 ;
    END
  END VSS
  PIN A1
    DIRECTION INPUT ;
    USE SIGNAL ;
    PORT
      LAYER M1 ;
        RECT 0.014 0.04 0.03 0.056 ;
    END
  END A1
  PIN A2
    DIRECTION INPUT ;
    USE SIGNAL ;
    PORT
      LAYER M1 ;
        RECT 0.058 0.04 0.074 0.056 ;
    END
  END A2
  PIN B1
    DIRECTION INPUT ;
    USE SIGNAL ;
    PORT
      LAYER M1 ;
        RECT 0.102 0.04 0.118 0.056 ;
    END
  END B1
  PIN ZN
    DIRECTION OUTPUT ;
    USE SIGNAL ;
    PORT
      LAYER M1 ;
        RECT 0.146 0.016 0.162 0.104 ;
    END
  END ZN
  PIN B2
    DIRECTION INPUT ;
    USE SIGNAL ;
    PORT
      LAYER M1 ;
        RECT 0.19 0.04 0.206 0.056 ;
    END
  END B2
  OBS
    LAYER M1 DESIGNRULEWIDTH 0 ;
      RECT 0.19 0.076 0.206 0.104 ;
      RECT 0.102 0.076 0.118 0.104 ;
      RECT 0.014 0.076 0.03 0.104 ;
    LAYER M0 DESIGNRULEWIDTH 0 ;
      RECT 0.009 0.02 0.21 0.03 ;
      RECT 0.171 0.042 0.208 0.054 ;
      RECT 0.104 0.042 0.136 0.054 ;
      RECT 0.06 0.042 0.092 0.054 ;
      RECT 0.009 0.042 0.048 0.054 ;
      RECT 0.009 0.066 0.209 0.078 ;
      RECT 0.185 0.09 0.209 0.1 ;
      RECT 0.143 0.09 0.167 0.1 ;
      RECT 0.099 0.09 0.123 0.1 ;
      RECT 0.011 0.09 0.035 0.1 ;
  END
END AOI22_X1

MACRO INV_X16
  CLASS CORE ;
  ORIGIN 0 0 ;
  FOREIGN INV_X16 0 0 ;
  SYMMETRY X Y ;
  SITE i3d_nsfet3nm ;
  SIZE 0.748 BY 0.12 ;
  PIN VDD
    DIRECTION INOUT ;
    USE POWER ;
    PORT
      LAYER M0 ;
        RECT -0.016 0.114 0.764 0.126 ;
    END
  END VDD
  PIN VSS
    DIRECTION INOUT ;
    USE GROUND ;
    PORT
      LAYER M0 ;
        RECT -0.016 -0.006 0.764 0.006 ;
    END
  END VSS
  PIN A
    DIRECTION INPUT ;
    USE SIGNAL ;
    PORT
      LAYER M1 ;
        RECT 0.058 0.016 0.074 0.104 ;
    END
  END A
  PIN ZN
    DIRECTION OUTPUT ;
    USE SIGNAL ;
    PORT
      LAYER M1 ;
        RECT 0.102 0.016 0.118 0.104 ;
    END
  END ZN
  OBS
    LAYER M1 DESIGNRULEWIDTH 0 ;
      RECT 0.718 0.016 0.734 0.104 ;
      RECT 0.674 0.016 0.69 0.104 ;
      RECT 0.63 0.016 0.646 0.104 ;
      RECT 0.586 0.016 0.602 0.104 ;
      RECT 0.542 0.016 0.558 0.104 ;
      RECT 0.498 0.016 0.514 0.104 ;
      RECT 0.454 0.016 0.47 0.104 ;
      RECT 0.41 0.016 0.426 0.104 ;
      RECT 0.366 0.016 0.382 0.104 ;
      RECT 0.322 0.016 0.338 0.104 ;
      RECT 0.278 0.016 0.294 0.104 ;
      RECT 0.234 0.016 0.25 0.104 ;
      RECT 0.19 0.016 0.206 0.104 ;
      RECT 0.146 0.016 0.162 0.104 ;
      RECT 0.014 0.016 0.03 0.104 ;
    LAYER M0 DESIGNRULEWIDTH 0 ;
      RECT 0.009 0.02 0.738 0.03 ;
      RECT 0.009 0.042 0.738 0.054 ;
      RECT 0.009 0.066 0.738 0.078 ;
      RECT 0.009 0.09 0.738 0.1 ;
  END
END INV_X16

MACRO OAI222_X1
  CLASS CORE ;
  ORIGIN 0 0 ;
  FOREIGN OAI222_X1 0 0 ;
  SYMMETRY X Y ;
  SITE i3d_nsfet3nm ;
  SIZE 0.22 BY 0.24 ;
  PIN VDD
    DIRECTION INOUT ;
    USE POWER ;
    PORT
      LAYER M0 ;
        RECT -0.016 -0.006 0.236 0.006 ;
        RECT -0.016 0.234 0.236 0.246 ;
    END
  END VDD
  PIN VSS
    DIRECTION INOUT ;
    USE GROUND ;
    PORT
      LAYER M0 ;
        RECT -0.016 0.114 0.236 0.126 ;
    END
  END VSS
  PIN B1
    DIRECTION INPUT ;
    USE SIGNAL ;
    PORT
      LAYER M1 ;
        RECT 0.014 0.184 0.03 0.2 ;
    END
  END B1
  PIN B2
    DIRECTION INPUT ;
    USE SIGNAL ;
    PORT
      LAYER M1 ;
        RECT 0.058 0.184 0.074 0.2 ;
    END
  END B2
  PIN C1
    DIRECTION INPUT ;
    USE SIGNAL ;
    PORT
      LAYER M1 ;
        RECT 0.102 0.184 0.118 0.2 ;
    END
  END C1
  PIN ZN
    DIRECTION OUTPUT ;
    USE SIGNAL ;
    PORT
      LAYER M1 ;
        RECT 0.146 0.016 0.162 0.224 ;
    END
  END ZN
  PIN C2
    DIRECTION INPUT ;
    USE SIGNAL ;
    PORT
      LAYER M1 ;
        RECT 0.19 0.184 0.206 0.2 ;
    END
  END C2
  PIN A1
    DIRECTION INPUT ;
    USE SIGNAL ;
    PORT
      LAYER M1 ;
        RECT 0.102 0.04 0.118 0.056 ;
    END
  END A1
  PIN A2
    DIRECTION INPUT ;
    USE SIGNAL ;
    PORT
      LAYER M1 ;
        RECT 0.19 0.04 0.206 0.056 ;
    END
  END A2
  OBS
    LAYER M1 DESIGNRULEWIDTH 0 ;
      RECT 0.19 0.076 0.206 0.104 ;
      RECT 0.102 0.076 0.118 0.104 ;
      RECT 0.058 0.088 0.074 0.152 ;
      RECT 0.19 0.136 0.206 0.164 ;
      RECT 0.102 0.136 0.118 0.164 ;
      RECT 0.014 0.136 0.03 0.164 ;
    LAYER M0 DESIGNRULEWIDTH 0 ;
      RECT 0.143 0.02 0.211 0.03 ;
      RECT 0.171 0.042 0.209 0.054 ;
      RECT 0.099 0.042 0.136 0.054 ;
      RECT 0.099 0.066 0.212 0.078 ;
      RECT 0.186 0.09 0.21 0.1 ;
      RECT 0.143 0.09 0.167 0.1 ;
      RECT 0.055 0.09 0.121 0.1 ;
      RECT 0.187 0.14 0.211 0.15 ;
      RECT 0.098 0.14 0.122 0.15 ;
      RECT 0.054 0.14 0.078 0.15 ;
      RECT 0.011 0.14 0.035 0.15 ;
      RECT 0.009 0.162 0.212 0.174 ;
      RECT 0.171 0.186 0.209 0.198 ;
      RECT 0.104 0.186 0.136 0.198 ;
      RECT 0.06 0.186 0.092 0.198 ;
      RECT 0.011 0.186 0.048 0.198 ;
      RECT 0.101 0.21 0.167 0.22 ;
  END
END OAI222_X1

END LIBRARY
